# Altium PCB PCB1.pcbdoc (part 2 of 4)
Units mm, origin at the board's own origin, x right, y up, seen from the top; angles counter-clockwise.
Board outline 96.27 x 122.17 mm, 4 copper layers (Top Layer, Inner1, Inner2, Bottom Layer); 135 components, 133 nets, 720 pads, 358 vias.

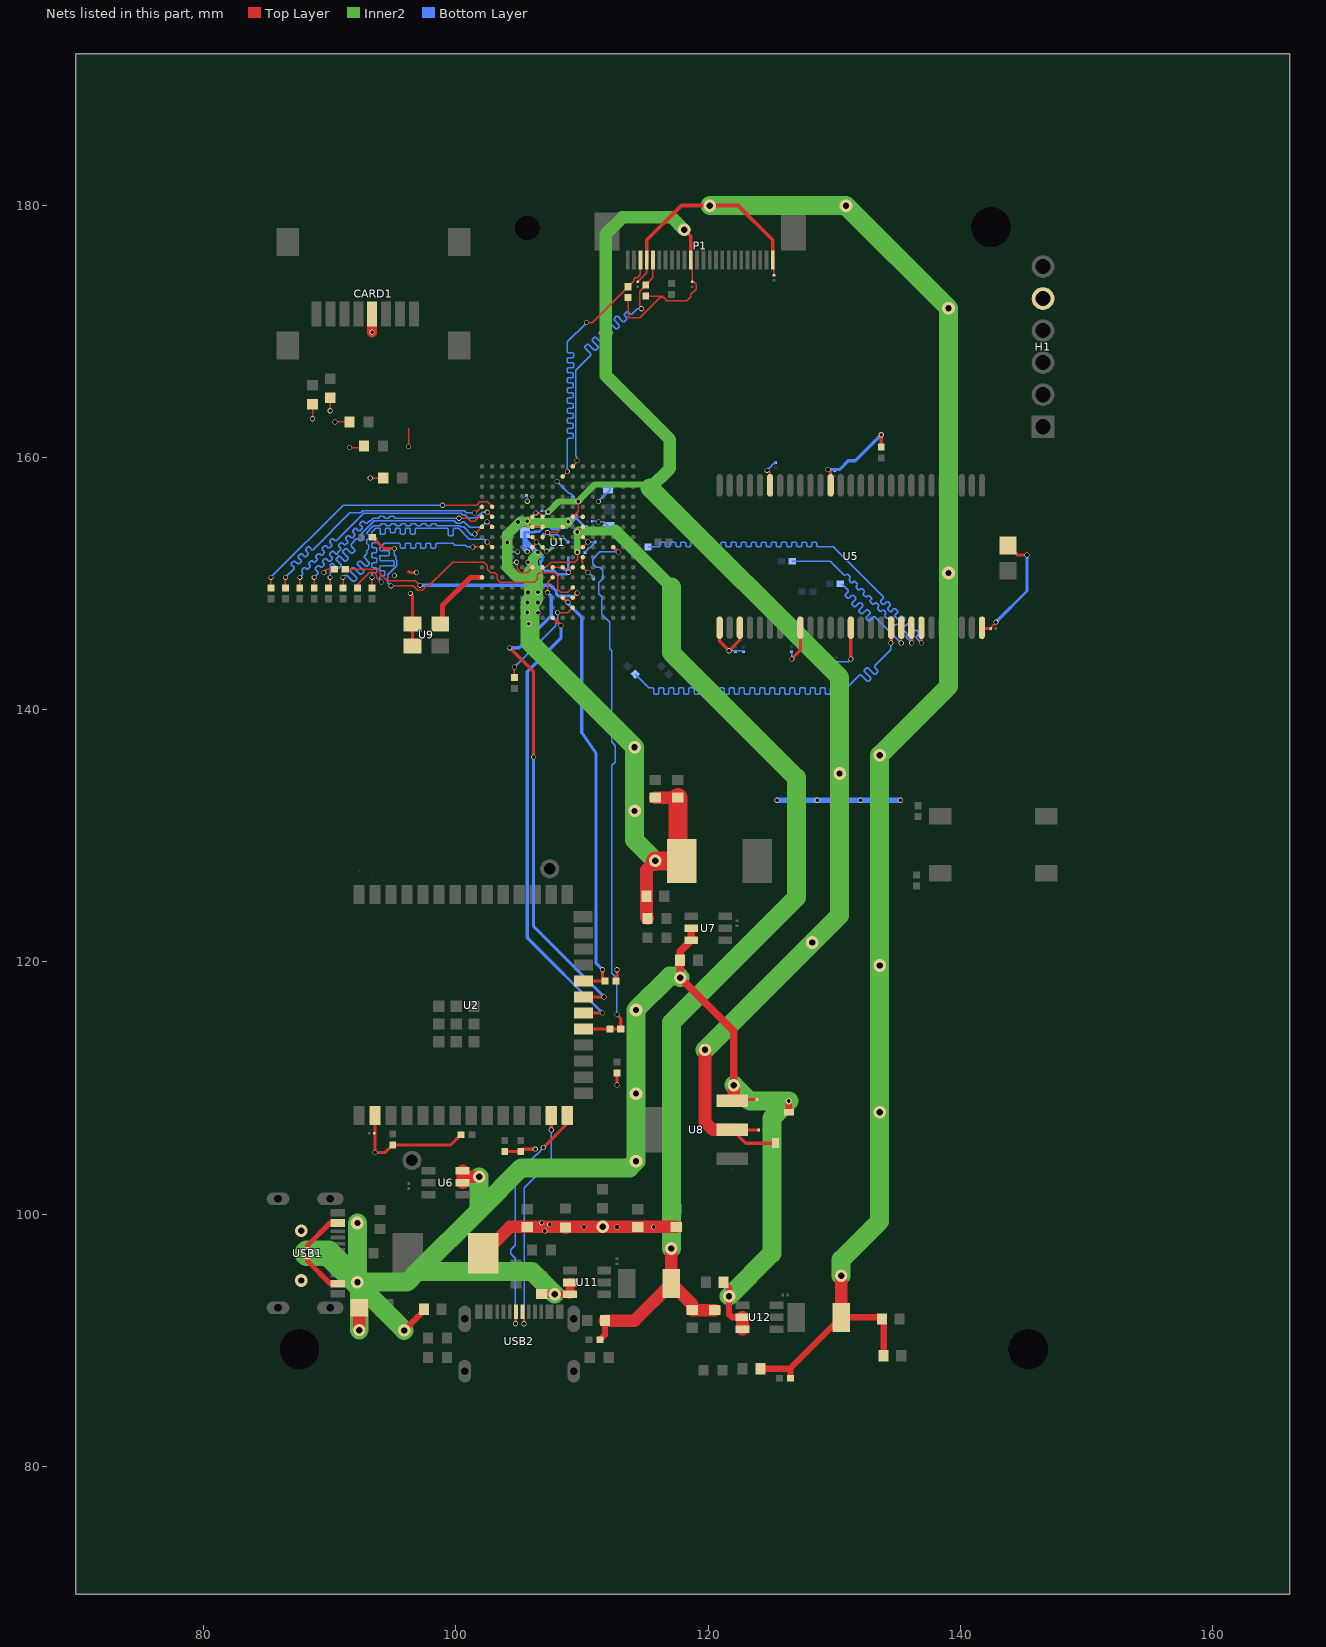
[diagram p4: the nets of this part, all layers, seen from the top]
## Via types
v1: diameter 0.4, hole 0.3, Top Layer to Bottom Layer, 324 vias
v2: diameter 1, hole 0.5, Top Layer to Bottom Layer, 33 vias
v3: diameter 0.5, hole 0.3, Top Layer to Bottom Layer, 1 vias

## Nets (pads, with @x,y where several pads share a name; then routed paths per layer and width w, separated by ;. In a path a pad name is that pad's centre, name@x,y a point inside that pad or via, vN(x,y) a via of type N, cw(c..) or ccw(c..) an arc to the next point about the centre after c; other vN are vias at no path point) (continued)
$1N71328: R50.2 U5.18 | length 41.7
  Top Layer w0.254: v1(134.493,145.288) 134.518,145.313 U5.18@134.518,146.504
  Bottom Layer w0.1: R50.2@114.225,142.823 115.316,141.732 115.616,141.732 115.687,141.661 115.687,141.295 115.757,141.224 116.016,141.224 116.087,141.295 116.087,141.661 116.157,141.732 116.416,141.732 116.487,141.661 116.487,141.295 116.557,141.224 116.816,141.224 116.887,141.295 116.887,141.661 116.957,141.732 117.216,141.732 117.287,141.661 117.287,141.295 117.357,141.224 117.616,141.224 117.687,141.295 117.687,141.661 117.757,141.732 118.016,141.732 118.087,141.661 118.087,141.295 118.157,141.224 118.416,141.224 118.487,141.295 118.487,141.661 118.557,141.732 118.816,141.732 118.887,141.661 118.887,141.295 118.957,141.224 119.216,141.224 119.287,141.295 119.287,141.661 119.357,141.732 119.616,141.732 119.687,141.661 119.687,141.295 119.757,141.224 120.016,141.224 120.087,141.295 120.087,141.661 120.157,141.732 120.416,141.732 120.487,141.661 120.487,141.295 120.557,141.224 120.816,141.224 120.887,141.295 120.887,141.661 120.957,141.732 121.216,141.732 121.287,141.661 121.287,141.295 121.357,141.224 121.616,141.224 121.687,141.295 121.687,141.661 121.757,141.732 122.016,141.732 122.087,141.661 122.087,141.295 122.157,141.224 122.416,141.224 122.487,141.295 122.487,141.661 122.557,141.732 122.816,141.732 122.887,141.661 122.887,141.295 122.957,141.224 123.216,141.224 123.287,141.295 123.287,141.661 123.357,141.732 123.616,141.732 123.687,141.661 123.687,141.295 123.757,141.224 124.016,141.224 124.087,141.295 124.087,141.661 124.157,141.732 124.416,141.732 124.487,141.661 124.487,141.295 124.557,141.224 124.816,141.224 124.887,141.295 124.887,141.661 124.957,141.732 125.216,141.732 125.287,141.661 125.287,141.295 125.357,141.224 125.616,141.224 125.687,141.295 125.687,141.661 125.757,141.732 126.016,141.732 126.087,141.661 126.087,141.295 126.157,141.224 126.416,141.224 126.487,141.295 126.487,141.661 126.557,141.732 126.816,141.732 126.887,141.661 126.887,141.295 126.957,141.224 127.216,141.224 127.287,141.295 127.287,141.661 127.357,141.732 127.616,141.732 127.687,141.661 127.687,141.295 127.757,141.224 128.016,141.224 128.087,141.295 128.087,141.661 128.157,141.732 128.416,141.732 128.487,141.661 128.487,141.295 128.557,141.224 128.816,141.224 128.887,141.295 128.887,141.661 128.957,141.732 129.216,141.732 129.287,141.661 129.287,141.295 129.357,141.224 129.616,141.224 129.687,141.295 129.687,141.661 129.757,141.732 130.985,141.732 132.014,142.761 132.114,142.761 132.625,142.25 132.725,142.25 132.908,142.433 132.908,142.533 132.397,143.044 132.397,143.144 132.579,143.327 132.679,143.327 133.191,142.816 133.291,142.816 133.473,142.998 133.473,143.098 133.199,143.373 133.199,143.473 134.493,144.768 v1(134.493,145.288)
$1N71371: R51.2 U5.19 | length 11.7
  Top Layer w0.1: v1(135.318,145.288) U5.19@135.318,146.504
  Bottom Layer w0.1: R51.2@130.627,149.958 131.119,149.466 131.119,149.366 130.881,149.127 130.881,149.027 131.064,148.844 131.164,148.844 131.402,149.083 131.502,149.083 131.714,148.871 131.714,148.771 131.395,148.453 131.395,148.353 131.578,148.17 131.678,148.17 131.997,148.489 132.097,148.489 132.28,148.306 132.28,148.206 131.961,147.887 131.961,147.787 132.144,147.604 132.244,147.604 132.563,147.923 132.663,147.923 132.845,147.74 132.845,147.64 132.527,147.321 132.527,147.221 132.71,147.039 132.81,147.039 133.128,147.357 133.228,147.357 135.17,145.415 135.191,145.415 v1(135.318,145.288)
$1N71457: R53.2 U5.21 | length 39.7
  Top Layer w0.254: v1(136.918,145.288) U5.21@136.918,146.504
  Bottom Layer w0.1: R53.2@115.241,152.908 116.151,152.908 116.222,152.979 116.222,153.218 116.293,153.289 116.551,153.289 116.622,153.218 116.622,152.979 116.693,152.908 116.951,152.908 117.022,152.979 117.022,153.218 117.093,153.289 117.351,153.289 117.422,153.218 117.422,152.979 117.493,152.908 117.751,152.908 117.822,152.979 117.822,153.218 117.893,153.289 118.151,153.289 118.222,153.218 118.222,152.979 118.293,152.908 118.551,152.908 118.622,152.979 118.622,153.218 118.693,153.289 118.951,153.289 119.022,153.218 119.022,152.979 119.093,152.908 119.351,152.908 119.422,152.979 119.422,153.218 119.493,153.289 119.751,153.289 119.822,153.218 119.822,152.979 119.893,152.908 120.151,152.908 120.222,152.979 120.222,153.218 120.293,153.289 120.551,153.289 120.622,153.218 120.622,152.979 120.693,152.908 120.951,152.908 121.022,152.979 121.022,153.218 121.093,153.289 121.351,153.289 121.422,153.218 121.422,152.979 121.493,152.908 121.751,152.908 121.822,152.979 121.822,153.218 121.893,153.289 122.151,153.289 122.222,153.218 122.222,152.979 122.293,152.908 122.551,152.908 122.622,152.979 122.622,153.218 122.693,153.289 122.951,153.289 123.022,153.218 123.022,152.979 123.093,152.908 123.351,152.908 123.422,152.979 123.422,153.218 123.493,153.289 123.751,153.289 123.822,153.218 123.822,152.979 123.893,152.908 124.151,152.908 124.222,152.979 124.222,153.218 124.293,153.289 124.551,153.289 124.622,153.218 124.622,152.979 124.693,152.908 124.951,152.908 125.022,152.979 125.022,153.218 125.093,153.289 125.351,153.289 125.422,153.218 125.422,152.979 125.493,152.908 125.751,152.908 125.822,152.979 125.822,153.218 125.893,153.289 126.151,153.289 126.222,153.218 126.222,152.979 126.293,152.908 126.551,152.908 126.622,152.979 126.622,153.218 126.693,153.289 126.951,153.289 127.022,153.218 127.022,152.979 127.093,152.908 127.351,152.908 127.422,152.979 127.422,153.218 127.493,153.289 127.751,153.289 127.822,153.218 127.822,152.979 127.893,152.908 128.151,152.908 128.222,152.979 128.222,153.218 128.293,153.289 128.551,153.289 128.622,153.218 128.622,152.979 128.693,152.908 129.921,152.908 133.892,148.937 133.892,148.837 133.68,148.626 133.68,148.526 133.863,148.343 133.963,148.343 134.175,148.554 134.275,148.554 134.458,148.371 134.458,148.271 134.246,148.06 134.246,147.96 134.429,147.777 134.529,147.777 134.74,147.989 134.84,147.989 135.023,147.806 135.023,147.706 134.812,147.494 134.812,147.394 134.995,147.211 135.095,147.211 135.306,147.423 135.406,147.423 135.589,147.24 135.589,147.14 135.377,146.929 135.377,146.829 135.56,146.646 135.66,146.646 135.872,146.857 135.972,146.857 136.155,146.674 136.155,146.574 135.943,146.363 135.943,146.263 136.126,146.08 136.226,146.08 136.437,146.292 136.537,146.292 136.72,146.109 136.72,146.009 136.509,145.797 136.509,145.697 v1(136.918,145.288)
$1N71500: R54.2 U5.20 | length 16.7
  Top Layer w0.254: U5.20@136.118,146.504 136.144,146.478 v1(136.144,145.288)
  Bottom Layer w0.1: R54.2@126.671,151.763 129.669,151.763 130.793,150.639 130.893,150.639 130.983,150.73 131.083,150.73 131.266,150.547 131.266,150.447 131.176,150.356 131.176,150.256 131.358,150.074 131.458,150.074 131.549,150.164 131.649,150.164 131.832,149.981 131.832,149.881 131.741,149.791 131.741,149.691 131.924,149.508 132.024,149.508 132.115,149.598 132.215,149.598 132.397,149.416 132.397,149.316 132.307,149.225 132.307,149.125 132.49,148.942 132.59,148.942 132.68,149.033 132.78,149.033 132.963,148.85 132.963,148.75 132.873,148.659 132.873,148.559 133.055,148.377 133.155,148.377 133.246,148.467 133.346,148.467 133.529,148.284 133.529,148.184 133.438,148.094 133.438,147.994 133.621,147.811 133.721,147.811 133.812,147.901 133.912,147.901 134.095,147.718 134.095,147.618 134.004,147.528 134.004,147.428 134.187,147.245 134.287,147.245 134.377,147.336 134.477,147.336 134.66,147.153 134.66,147.053 134.57,146.962 134.57,146.862 134.753,146.679 134.853,146.679 134.943,146.77 135.043,146.77 135.226,146.587 135.226,146.487 135.135,146.397 135.135,146.297 135.318,146.114 135.418,146.114 135.509,146.204 135.609,146.204 135.792,146.021 135.792,145.921 135.701,145.831 135.701,145.731 v1(136.144,145.288)
$2N5507: R23.2 U1.P10 | length 20.1
  Top Layer w0.1: R23.2@91.238,151.13 93.853,151.13 93.959,151.024 93.959,150.836 94.575,150.22 96.795,150.22 v1(97.155,149.86)
  Top Layer w0.254: U1.P10@109.277,148.889 109.601,149.213 v1@109.601,149.225
  Bottom Layer w0.254: v1(97.155,149.86) 107.507,149.86 107.986,149.381 107.986,149.159 108.127,149.018 109.073,149.018 109.173,148.918 109.294,148.918 v1(109.622,149.246)
$2N5509: R24.2 U1.N10 | length 24
  Top Layer w0.1: v1(94.869,149.818) 96.628,149.818 96.988,149.458 97.322,149.458 97.682,149.818 97.875,149.818 99.119,151.062 99.119,151.067 99.759,151.707 102.199,151.707 102.495,151.411 102.495,151.131 102.755,150.871 103.091,150.871 103.295,150.667 103.295,150.331 103.519,150.107 105.435,150.107 105.442,150.114 105.912,150.114 105.919,150.107 106.235,150.107 106.459,150.331 106.459,150.689 106.641,150.871 107.835,150.871 108.095,150.611 108.095,149.531 108.319,149.307 108.895,149.307 U1.N10@109.277,149.689
  Top Layer w0.254: R24.2@93.397,153.67 94.286,152.781 v1(95.123,152.781)
  Bottom Layer w0.1: v1(94.869,149.818) 94.615,150.072 94.615,150.697 95.323,151.405 95.323,151.829 95.25,151.902 95.25,152.146 95.123,152.273 v1(95.123,152.781)
$2N5511: R25.2 U1.R10 | length 7.9
  Top Layer w0.1: R25.2@104.648,142.546 v1(104.648,143.383) ; v1(108.077,147.701) 108.889,147.701 U1.R10@109.277,148.089
  Bottom Layer w0.1: v1(104.648,143.383) 107.929,146.664 107.929,146.852 108.077,147 v1(108.077,147.701)
+1V1: C25.2 C27.2 C28.2 C41.1 C42.1 C43.1 C44.1 C49.1 C53.1 C54.1 C61.1 L2.2 R15.2 U1.G6 U1.G7 U1.L8 U1.L9 U1.L10 | length 71.4
  Top Layer w0.1: v1@105.664,154.94 105.664,154.902 U1.G6@106.077,154.489 U1.G7@106.877,154.489 ; U1.L8@107.677,151.289 U1.L9@108.477,151.289 108.543,151.289 v1(108.936,150.897) 109.277,151.238 U1.L10@109.277,151.289
  Top Layer w1: R15.2@115.198,123.444 115.124,123.518 C25.2@115.124,125.222 115.124,127.316 v2(115.824,128.016) ; C27.2@115.824,133.031 C28.2@117.602,133.031
  Top Layer w1.5: v2(115.824,128.016) L2.2@117.904,128.016 117.602,128.318 C28.2@117.602,133.031
  Inner2 w0.7: 105.232,154.932 v1(105.672,154.932)
  Inner2 w0.8: v1(104.086,153.249) v1@104.077,153.258 ; 105.232,154.932 105.21,154.909 105.111,154.909 104.077,153.875 v1@104.077,153.258 ; v1@105.672,154.909 105.777,154.805 106.053,154.805 106.069,154.789 108.815,154.789 v1(108.92,154.894) ; v1@106.436,152.302 106.125,151.99 106.125,150.859 105.705,150.439 104.877,150.439 104.077,151.239 v1@104.077,153.258
  Inner2 w1.5: 106.125,150.859 106.172,150.812 106.172,148.785 105.895,148.508 105.895,145.311 v2(114.173,137.033) v2(114.173,131.972) 114.173,129.667 v2(115.824,128.016)
  Bottom Layer w0.2: 105.475,153.518 C61.1@105.475,154.051 106.24,154.051 C41.1@106.299,154.11 106.607,154.11 106.986,154.489 107.461,154.489 107.661,154.289 108.082,154.289 C42.1@108.342,154.548 108.458,154.432 108.78,154.432 109.542,155.194 ; v1(106.514,152.479) 106.642,152.479 106.736,152.385 106.736,152.381 106.842,152.275 106.842,151.859 C54.1@106.748,151.765 106.748,151.316 107.061,151.003 107.819,151.003 108.073,150.749 108.788,150.749 108.801,150.762 v1@108.936,150.762 ; C53.1@108.653,151.13 108.78,151.003 108.839,151.003 108.907,150.935 C49.1@108.907,152.019 ; C43.1@109.542,155.448 109.542,155.194 ; C44.1@110.558,154.178 110.525,154.211 110.525,154.392 110.377,154.54 110.196,154.54 109.542,155.194
  Bottom Layer w0.4: 105.475,153.409 106.405,152.479 v1(106.514,152.479) ; 105.475,153.518 105.475,152.716 v1(105.666,152.525)
  other v1: 105.791,146.812 105.664,147.701 106.527,147.689 106.526,148.489 105.661,148.508 105.726,149.289 106.508,149.306 105.727,151.69 104.926,154.888
+1V8: C29.1 C32.2 C35.1 C62.1 C63.1 P1.11 pad.55@123.394,105.627 R38.2 R39.2 U1.F10 U1.F11 U8.2 | length 126.3
  Top Layer w0.1: v1(109.709,156.504) 109.709,156.262 109.695,156.247 109.695,155.931 109.709,155.917 109.709,155.721 U1.F10@109.277,155.289 U1.F11@110.077,155.289 ; R38.2@113.665,172.668 113.665,172.205 113.661,172.201 113.661,171.2 113.792,171.069 114.574,171.069 116.173,172.668 116.509,172.668 ; R39.2@115.062,172.795 116.382,172.795 116.509,172.668 ; P1.11@118.634,175.655 118.733,175.557 118.733,174.458 118.745,174.446 C35.1@118.745,173.931 ; 118.856,173.931 119.057,173.73 119.057,173.352 118.639,172.934 118.639,172.756 118.321,172.437 116.74,172.437 116.509,172.668
  Top Layer w0.254: C29.1@124.011,106.68 121.943,106.68 122.996,105.627 pad.55@123.394,105.627 C32.2@125.349,105.627
  Top Layer w0.3: v2(118.11,178.054) 118.634,177.53 P1.11@118.634,175.655
  Top Layer w1: v2(119.761,113.03) 119.761,107.315 120.367,106.709 U8.2@121.914,106.709
  Inner2 w0.5: v1(107.325,155.689) 107.362,155.689 108.178,156.504 v1(109.709,156.504) 109.888,156.683 109.888,156.713 111.036,157.861 115.379,157.861
  Inner2 w1: 115.411,157.575 116.967,159.131 116.967,161.417 111.887,166.497 111.887,177.71 113.21,179.033 117.131,179.033 v2(118.11,178.054)
  Inner2 w1.5: 115.411,157.575 130.429,142.558 v2(130.429,134.939) 130.429,123.698 v2(128.27,121.539) v2(119.761,113.03)
  Bottom Layer w0.1: C63.1@106.807,155.761 107.253,155.761 v1(107.325,155.689) 106.934,155.298 C62.1@106.934,155.262
+2V5: C65.2 C67.2 C68.2 L3.2 R41.2 U1.G11 U1.L7 | length 91.3
  Top Layer w0.1: U1.L7@106.877,151.289 107.137,151.289 107.555,151.707 109.435,151.707 109.659,151.931 109.659,152.247 109.629,152.277 v1(109.629,152.489) ; v1(109.629,154.089) 110.029,154.489 U1.G11@110.077,154.489
  Top Layer w0.5: R41.2@111.431,90.043 111.825,90.437 C65.2@111.825,91.567
  Top Layer w1: C65.2@111.825,91.567 114.17,91.567 L3.2@117.091,94.488 ; v2(117.091,97.282) L3.2@117.091,94.488 ; C67.2@120.523,92.394 C68.2@118.745,92.394 118.745,92.834 L3.2@117.091,94.488
  Inner2 w0.5: v1(109.629,152.489) v1(109.629,154.089)
  Inner2 w0.7: v1(109.629,154.089) 109.718,154.178 112.649,154.178
  Inner2 w1: 112.649,154.178 117.091,149.736
  Inner2 w1.5: v2(117.091,97.282) 117.091,115.186 127,125.095 127,134.62 117.091,144.529 117.091,149.736
+2V8: C34.1 C70.2 C72.2 C73.2 C74.1 L4.2 P1.4 P1.24 R47.2 | length 139.5
  Top Layer w0.1: C34.1@114.427,173.931 115.135,174.639 P1.4@115.135,175.655 ; P1.24@125.136,175.652 125.222,175.566 C74.1@125.222,174.439
  Top Layer w0.3: P1.4@115.135,175.655 115.135,177.23 117.885,179.98 122.383,179.98 125.136,177.227 P1.24@125.136,175.652
  Top Layer w0.5: C70.2@124.144,87.757 126.489,87.757 ; R47.2@126.544,86.995 126.544,87.702 126.489,87.757 ; C73.2@133.793,91.694 133.666,91.821 L4.2@130.553,91.821 126.489,87.757 ; C72.2@133.92,88.773 C73.2@133.92,91.567
  Top Layer w1: L4.2@130.556,91.824 v2(130.556,95.123)
  Inner2 w1.5: v2(120.142,179.959) v2(130.937,179.959) v2(139.065,171.831) v2(139.065,150.833) 139.065,141.859 v2(133.604,136.398) v2(133.604,119.716) v2(133.604,108.091) 133.604,99.441 130.556,96.393 v2(130.556,95.123)
+3V3: C8.1 C10.1 C11.1 C12.1 C13.1 C14.1 C15.2 C16.2 C17.2 C19.2 C22.2 C23.2 C37.1 C39.1 C40.1 C45.1 C46.1 C47.1 C48.1 C50.1 C51.1 C52.1 C55.1 C56.1 C57.1 C58.1 C59.1 CARD1.4 H1.5 L1.2 R1.2 R3.1 R4.1 R5.2 R7.2 R11.2 R16.2 R17.2 R18.2 R19.2 R20.2 R21.2 R22.2 R23.1 U1.F6 U1.F7 U1.G9 U1.H6 U1.H7 U1.H11 U1.J6 U1.J7 U1.J11 U1.K11 U1.L6 U1.L11 U2.2 U5.1 U5.3 U5.9 U5.14 U5.27 U5.43 U5.49 U9.1 U9.4 | length 113.5
  Top Layer w0.1: v1(88.646,163.068) R19.2@88.646,164.22 ; v1(89.537,150.887) 89.78,151.13 R23.1@90.372,151.13 ; v1(90.043,163.703) R18.2@90.043,164.728 ; v1(90.424,162.814) R20.2@91.576,162.814 ; v1(91.567,160.782) 92.592,160.782 R17.2@92.719,160.909 ; v1(93.218,158.369) R16.2@94.243,158.369 ; v1@96.275,160.909 96.275,162.306 ; v1(104.829,151.689) 104.859,151.659 104.859,151.167 105.15,150.876 105.664,150.876 U1.L6@106.077,151.289 ; U1.J6@106.077,152.889 106.405,153.217 v1(106.405,153.288) 106.405,153.361 U1.H6@106.077,153.689 ; U1.F6@106.077,155.289 106.345,155.557 v1(106.345,155.607) 106.559,155.607 U1.F7@106.877,155.289 ; U1.J7@106.877,152.889 107.188,152.578 v1@107.188,152.527 ; U1.H7@106.877,153.689 106.926,153.689 v1(107.274,154.037) 107.484,154.037 107.519,154.071 107.835,154.071 107.881,154.025 108.013,154.025 U1.G9@108.477,154.489 ; U1.K11@110.077,152.089 110.077,151.962 109.982,151.867 109.982,151.765 110.077,151.67 U1.L11@110.077,151.289 v1(110.49,150.876) ; U1.J11@110.077,152.889 110.477,153.289 v1(110.49,153.289) 110.09,153.689 U1.H11@110.077,153.689 ; v1(124.674,158.977) 124.741,158.977 124.918,158.8 U5.49@124.918,157.788 ; C14.1@142.426,146.431 142.509,146.514 142.509,146.625 142.627,146.743 142.738,146.743 142.816,146.821 v1(142.816,146.939)
  Top Layer w0.254: U2.2@93.721,107.836 93.599,107.714 v1(93.599,104.902) 94.413,104.902 R7.2@94.996,105.485 99.591,105.485 R5.2@100.405,106.299 ; 96.271,150.952 96.346,150.876 v1(96.901,150.876) ; v1(96.393,149.225) 96.563,149.055 U9.4@96.563,146.798 U9.1@96.563,145.048 ; R21.2@103.886,104.977 R22.2@105.156,104.977 105.335,105.156 v1(106.299,105.156) ; R3.1@112.701,118.491 112.776,118.566 v1(112.776,119.38) ; v1(112.776,110.236) R4.1@112.776,111.2 ; U5.1@120.918,146.631 120.918,145.422 v1(121.666,144.674) 122.518,145.526 U5.3@122.518,146.504 ; v1(126.638,144.028) 127.318,144.707 U5.9@127.318,146.504 ; v1(129.5,159.044) 129.718,158.826 U5.43@129.718,157.788 ; v1(131.318,144.018) U5.14@131.318,146.504 ; R1.2@133.731,160.834 v1(133.731,161.798) ; U5.27@141.718,146.504 141.791,146.431 C14.1@142.426,146.431 ; C8.1@143.764,153.019 144.51,152.273 v1(145.288,152.273)
  Top Layer w0.8: v1(93.372,169.926) CARD1.4@93.372,171.374
  Top Layer w1: L1.2@102.187,96.901 104.281,98.995 C19.2@105.664,98.995 108.659,98.995 R11.2@108.712,98.942 108.765,98.995 v1(110.161,98.995) v2(111.647,98.995) v1(112.775,98.995) C23.2@114.427,98.995 v1(115.692,98.995) C22.2@117.475,98.995
  Inner2 w0.1: v1(106.405,153.288) 106.468,153.288 v1(107.188,152.568) 107.412,152.568 108.041,153.198 108.041,153.269 v1(107.274,154.037)
  Bottom Layer w0.1: C51.1@104.208,151.638 104.778,151.638 v1(104.829,151.689) ; C56.1@104.462,152.527 104.886,152.527 v1(104.894,152.519) ; C37.1@105.605,156.972 105.664,156.913 v1(105.664,156.524) ; C45.1@106.934,153.865 107.102,153.865 v1(107.274,154.037) 107.455,153.855 108.071,153.855 108.189,153.737 108.189,153.626 C46.1@108.272,153.543 108.644,153.543 C47.1@108.898,153.289 ; v1(107.188,152.568) 107.288,152.568 C57.1@107.628,152.908 ; C50.1@108.018,156.464 109.018,156.464 109.205,156.651 109.205,156.762 C39.1@109.288,156.845 109.288,156.956 109.087,157.157 108.961,157.157 v1(108.029,158.089) ; C52.1@110.236,152.468 C55.1@111.057,153.289 v1(110.49,153.289) ; v1(110.49,150.876) 110.686,150.68 110.738,150.68 110.939,150.479 C48.1@110.939,150.368 ; C40.1@110.812,154.94 111.274,154.94 v1(111.323,154.89) 111.745,154.89 C59.1@112.141,154.494 ; v1(111.301,156.512) 112.206,157.417 C58.1@112.206,157.607 ; v1(121.666,144.674) 121.974,144.674 121.98,144.668 122.726,144.668 C11.1@122.809,144.585 ; v1(124.674,158.977) 125.037,159.34 125.037,159.379 125.155,159.497 125.266,159.497 C16.2@125.349,159.58 ; C12.1@126.619,144.585 126.638,144.566 v1(126.638,144.028) ; C13.1@129.91,143.88 130.028,143.88 130.106,143.802 131.102,143.802 v1(131.318,144.018)
  Bottom Layer w0.254: v1(129.5,159.044) 130.427,159.044 131.12,159.737 131.67,159.737 v1(133.731,161.798) ; v1(142.816,146.939) 145.288,149.411 v1(145.288,152.273)
  Bottom Layer w0.4: v1(125.476,132.821) v1(128.651,132.821) v1(132.08,132.821) v1(135.255,132.821)
  other v1: 107.061,98.679 107.442,99.187 106.807,99.314 95.123,150.636 96.241,160.876
+5V: C20.2 C26.2 C30.1 C31.2 C33.2 C66.2 C71.2 U6.2 U6.3 U7.2 U7.3 U8.3 U11.2 U11.3 U12.2 U12.3 USB1.A4B9 USB1.B4A9 | length 137.8
  Top Layer w0.254: U8.3@122.301,109.093 C30.1@123.884,109.093
  Top Layer w0.4: USB1.B4A9@90.627,94.501 90.03,94.501 88.227,96.304 88.227,97.508 90.02,99.301 USB1.A4B9@90.627,99.301
  Top Layer w0.5: v2(95.904,90.786) 97.471,92.353 C20.2@97.471,92.456 ; C66.2@106.807,93.661 v2(107.842,93.661) 109.042,93.661 U11.3@109.066,93.637 ; C71.2@121.223,94.615 121.666,94.172 v2(121.666,93.492) 121.666,92.075 121.92,91.821 U12.2@122.729,91.821 ; C31.2@126.402,108.077 v3(126.402,108.966)
  Top Layer w0.6: U7.2@118.665,122.682 U7.3@118.665,121.732 117.791,120.858 C26.2@117.791,120.142 v2(117.791,118.745) 122.047,114.489 v2(122.047,110.236)
  Top Layer w0.7: U11.3@109.066,93.637 U11.2@109.066,94.587
  Top Layer w1: v2(92.345,90.805) C33.2@92.345,92.583 ; U6.2@100.537,102.491 100.537,102.97 ; U6.3@100.537,103.439 100.537,102.97 ; v2(101.854,102.97) 100.537,102.97 ; U8.3@121.914,109.009 122.047,109.142 v2(122.047,110.236) ; U12.3@122.729,90.871 U12.2@122.729,91.819
  Inner2 w1.5: v2(92.202,99.301) v2(92.202,94.615) 96.139,94.615 96.987,95.463 ; v2(92.345,90.805) 92.345,94.091 92.202,94.234 92.456,94.234 v2(95.904,90.786) ; v2(101.854,102.97) 101.854,100.33 ; v2(107.842,93.661) 106.04,95.463 96.987,95.463 ; v2(117.791,118.745) 117.664,118.872 116.964,118.872 v2(114.286,116.194) v2(114.286,109.562) v2(114.286,104.198) 113.761,103.673 105.197,103.673 101.854,100.33 ; v2(121.666,93.492) 125.062,96.888 125.062,107.626 v3(126.402,108.966) 123.317,108.966 v2(122.047,110.236) ; 96.987,95.463 101.854,100.33
  Inner2 w2: v2(88.213,96.901) 89.916,96.901 v2(92.202,94.615)
  other v2: 87.757,94.742 87.757,98.679
CCLK: R6.1 R6.2 U1.J14 U2.19 | length 44.6
  Top Layer w0.254: U2.19@110.241,114.681 R6.1@112.216,114.681 R6.2@113.082,114.681 113.082,115.518 v1(112.776,115.824) ; U1.J14@112.477,152.889 112.86,152.506 v1(112.903,152.506)
  Bottom Layer w0.1: v1(112.776,115.824) 112.776,118.703 112.374,119.105 112.374,135.577 112.649,135.852 112.649,137.16 112.395,137.414 112.374,137.414 112.374,144.674 112.222,144.826 112.222,146.928 111.564,147.586 111.564,148.951 111.335,149.18 111.335,150.07 111.654,150.389 111.654,151.043 111.419,151.278 111.133,151.278 110.848,151.562 110.848,151.93 111.424,152.506 v1(112.903,152.506)
CRYSTAL: U1.M1 U9.3 | length 5.6
  Top Layer w0.4: U9.3@98.763,146.798 98.933,146.968 98.933,148.256 101.162,150.485 101.209,150.485 101.213,150.489 U1.M1@102.077,150.489
D0: R26.1 U1.E2 | length 21
  Top Layer w0.1: R26.1@85.344,149.658 v1(85.344,150.495) ; v1@98.933,156.21 101.658,156.21 101.919,156.471 102.495,156.471 U1.E2@102.877,156.089
  Bottom Layer w0.1: v1(85.344,150.495) 91.059,156.21 v1(98.943,156.21)
D1: R27.1 U1.E1 | length 21.1
  Top Layer w0.1: R27.1@86.487,149.658 v1(86.487,150.495) ; v1(101.473,155.604) 101.592,155.604 U1.E1@102.077,156.089
  Bottom Layer w0.1: v1(86.487,150.495) 87.172,151.18 87.172,151.28 86.955,151.498 86.955,151.598 87.137,151.78 87.237,151.78 87.455,151.563 87.555,151.563 87.738,151.746 87.738,151.846 87.52,152.063 87.52,152.163 87.703,152.346 87.803,152.346 88.021,152.129 88.121,152.129 88.303,152.311 88.303,152.411 88.086,152.629 88.086,152.729 88.269,152.912 88.369,152.912 88.586,152.694 88.686,152.694 91.596,155.604 92.456,155.604 92.634,155.782 100.666,155.782 100.844,155.604 v1(101.473,155.604)
D2: R28.1 U1.F2 | length 21
  Top Layer w0.1: R28.1@87.63,149.658 v1(87.63,150.495) ; v1(102.486,155.659) 102.507,155.659 U1.F2@102.877,155.289
  Bottom Layer w0.1: v1(87.63,150.495) 87.884,150.749 87.884,150.849 87.78,150.953 87.78,151.053 87.963,151.236 88.063,151.236 88.167,151.132 88.267,151.132 88.45,151.315 88.45,151.415 88.346,151.519 88.346,151.619 88.529,151.802 88.629,151.802 88.733,151.698 88.833,151.698 89.015,151.88 89.015,151.98 88.911,152.084 88.911,152.184 89.094,152.367 89.194,152.367 89.298,152.263 89.398,152.263 89.581,152.446 89.581,152.546 89.427,152.7 89.427,152.8 89.61,152.983 89.71,152.983 89.864,152.829 89.964,152.829 90.147,153.012 90.147,153.112 89.993,153.266 89.993,153.366 90.176,153.549 90.276,153.549 90.43,153.395 90.53,153.395 92.717,155.582 100.414,155.582 100.524,155.473 100.692,155.473 100.963,155.202 101.64,155.202 102.096,155.659 v1(102.486,155.659)
D3: R29.1 U1.F1 | length 21
  Top Layer w0.1: R29.1@88.773,149.658 v1(88.773,150.495) ; v1(100.248,155.18) 100.947,155.18 101.179,154.948 101.513,154.948 101.871,155.306 102.06,155.306 U1.F1@102.077,155.289
  Bottom Layer w0.1: v1(88.773,150.495) 89.092,150.814 89.092,150.914 88.875,151.132 88.875,151.232 89.058,151.415 89.158,151.415 89.277,151.295 89.377,151.295 89.56,151.478 89.56,151.578 89.44,151.697 89.44,151.797 89.623,151.98 89.723,151.98 89.941,151.763 90.041,151.763 90.224,151.946 90.224,152.046 90.006,152.263 90.006,152.363 90.189,152.546 90.289,152.546 90.507,152.329 90.607,152.329 90.659,152.381 90.659,152.477 90.871,152.69 90.871,152.79 90.702,152.959 90.702,153.059 90.885,153.242 90.985,153.242 91.154,153.072 91.254,153.072 91.437,153.255 91.437,153.355 91.268,153.525 91.268,153.625 91.45,153.807 91.55,153.807 91.72,153.638 91.82,153.638 92.003,153.821 92.003,153.921 91.833,154.09 91.833,154.19 92.016,154.373 92.116,154.373 92.285,154.204 92.385,154.204 92.568,154.387 92.568,154.487 92.399,154.656 92.399,154.756 92.582,154.939 92.682,154.939 92.851,154.769 92.951,154.769 93.16,154.978 93.256,154.978 93.458,155.18 93.853,155.18 93.924,155.251 93.924,155.277 93.995,155.348 94.253,155.348 94.324,155.277 94.324,155.251 94.395,155.18 94.653,155.18 94.724,155.251 94.724,155.277 94.795,155.348 95.053,155.348 95.124,155.277 95.124,155.251 95.195,155.18 v1(100.248,155.18)
D4: R30.1 U1.G2 | length 21
  Top Layer w0.1: R30.1@89.916,149.658 90.043,149.785 v1(90.043,150.495) ; v1(102.471,154.892) 102.474,154.892 U1.G2@102.877,154.489
  Bottom Layer w0.1: v1(90.043,150.495) 90.043,151.482 90.189,151.628 90.207,151.628 90.619,151.216 90.719,151.216 90.902,151.399 90.902,151.499 90.49,151.911 90.49,151.929 90.755,152.194 90.773,152.194 91.185,151.782 91.285,151.782 91.468,151.965 91.468,152.065 91.056,152.477 91.056,152.577 91.239,152.76 91.339,152.76 91.701,152.398 91.801,152.398 91.983,152.581 91.983,152.681 91.694,152.97 91.694,153.133 92.12,153.559 92.22,153.559 92.388,153.391 92.488,153.391 92.671,153.573 92.671,153.673 92.503,153.842 92.503,153.942 93.541,154.98 99.879,154.98 100.081,154.778 100.414,154.778 100.541,154.905 100.65,154.905 101.102,154.453 102.031,154.453 v1(102.471,154.892)
D5: R31.1 U1.G1 | length 21
  Top Layer w0.1: R31.1@91.059,149.658 v1(91.059,150.495) ; v1(101.507,153.924) 101.512,153.924 U1.G1@102.077,154.489
  Bottom Layer w0.1: v1(91.059,150.495) 91.238,150.674 91.338,150.674 91.847,150.165 91.947,150.165 92.13,150.348 92.13,150.448 91.621,150.957 91.621,151.057 91.803,151.239 91.903,151.239 92.413,150.73 92.513,150.73 92.695,150.913 92.695,151.013 92.186,151.522 92.186,151.622 92.35,151.786 92.45,151.786 92.862,151.374 92.962,151.374 93.145,151.556 93.145,151.656 92.733,152.069 92.733,152.169 92.933,152.369 92.933,152.627 93.004,152.697 93.045,152.697 93.116,152.768 93.116,153.027 93.045,153.097 93.004,153.097 92.933,153.168 92.933,153.427 93.004,153.497 93.045,153.497 93.116,153.568 93.116,153.827 93.045,153.897 93.004,153.897 92.933,153.968 92.933,154.042 93.379,154.488 93.401,154.488 93.491,154.578 93.976,154.578 94.047,154.649 94.047,154.68 94.118,154.751 94.376,154.751 94.447,154.68 94.447,154.649 94.518,154.578 94.776,154.578 94.847,154.649 94.847,154.68 94.918,154.751 95.176,154.751 95.247,154.68 95.247,154.649 95.318,154.578 95.576,154.578 95.647,154.649 95.647,154.68 95.718,154.751 95.976,154.751 96.047,154.68 96.047,154.649 96.118,154.578 96.376,154.578 96.447,154.649 96.447,154.68 96.518,154.751 96.776,154.751 96.847,154.68 96.847,154.649 96.918,154.578 97.176,154.578 97.247,154.649 97.247,154.68 97.318,154.751 97.576,154.751 97.647,154.68 97.647,154.649 97.718,154.578 97.976,154.578 98.047,154.649 98.047,154.68 98.118,154.751 98.376,154.751 98.447,154.68 98.447,154.649 98.518,154.578 100.302,154.578 100.392,154.488 100.621,154.488 101.275,153.834 101.417,153.834 v1(101.507,153.924)
D6: R32.1 U1.J1 | length 20.9
  Top Layer w0.1: R32.1@92.202,149.658 92.202,149.921 93.178,150.897 93.512,150.897 93.747,150.662 93.747,150.474 v1(94.107,150.114) ; v1(101.346,152.908) 102.058,152.908 U1.J1@102.077,152.889
  Bottom Layer w0.1: v1(94.107,150.114) 93.959,150.262 93.959,150.546 94.03,150.617 94.294,150.617 94.365,150.687 94.365,150.946 94.294,151.017 94.03,151.017 93.959,151.087 93.959,151.346 94.03,151.417 95.052,151.417 95.123,151.487 95.123,151.746 95.052,151.817 94.03,151.817 93.959,151.887 93.959,152.146 94.03,152.217 94.671,152.217 94.742,152.287 94.742,152.546 94.671,152.617 94.03,152.617 93.959,152.687 93.959,152.821 94.321,153.183 95.539,153.183 95.61,153.112 95.61,152.852 95.68,152.781 95.939,152.781 96.01,152.852 96.01,153.112 96.08,153.183 96.339,153.183 96.41,153.112 96.41,152.852 96.48,152.781 96.739,152.781 96.81,152.852 96.81,153.112 96.88,153.183 97.139,153.183 97.21,153.112 97.21,152.852 97.28,152.781 97.539,152.781 97.61,152.852 97.61,153.112 97.68,153.183 97.939,153.183 98.01,153.112 98.01,152.852 98.08,152.781 98.339,152.781 98.41,152.852 98.41,153.112 98.48,153.183 99.801,153.183 99.928,153.056 100.751,153.056 100.899,152.908 v1(101.346,152.908)
D7: R34.1 U1.J2 | length 21
  Top Layer w0.1: R34.1@93.345,149.658 v1(93.345,150.495) ; v1(102.489,153.289) 102.489,153.277 U1.J2@102.877,152.889
  Bottom Layer w0.1: v1(93.345,150.495) 93.345,150.769 93.416,150.84 93.659,150.84 93.73,150.911 93.73,151.169 93.659,151.24 93.416,151.24 93.345,151.311 93.345,151.569 93.416,151.64 93.659,151.64 93.73,151.711 93.73,151.969 93.659,152.04 93.416,152.04 93.345,152.111 93.345,152.369 93.416,152.44 93.659,152.44 93.73,152.511 93.73,152.769 93.659,152.84 93.416,152.84 93.345,152.911 93.345,153.169 93.416,153.24 93.659,153.24 93.73,153.311 93.73,153.569 93.659,153.64 93.416,153.64 93.345,153.711 93.345,154.051 93.672,154.378 93.921,154.378 93.991,154.307 93.991,153.969 94.062,153.898 94.321,153.898 94.391,153.969 94.391,154.307 94.462,154.378 94.721,154.378 94.791,154.307 94.791,154.11 94.862,154.04 95.121,154.04 95.191,154.11 95.191,154.307 95.262,154.378 95.521,154.378 95.591,154.307 95.591,153.969 95.662,153.898 95.921,153.898 95.991,153.969 95.991,154.307 96.062,154.378 96.321,154.378 96.391,154.307 96.391,153.969 96.462,153.898 96.721,153.898 96.791,153.969 96.791,154.307 96.862,154.378 99.316,154.378 99.386,154.307 99.386,153.868 99.457,153.797 99.716,153.797 99.786,153.868 99.786,154.307 99.857,154.378 100.22,154.378 101.076,153.522 102.256,153.522 v1(102.489,153.289)
DIN: U1.T8 U2.20 | length 36.6
  Top Layer w0.254: U1.T8@107.677,147.289 107.727,147.289 v1(108.331,146.685) ; U2.20@110.241,115.951 v1(111.633,115.951)
  Bottom Layer w0.254: v1(108.331,146.685) 108.331,145.669 105.664,143.002 105.664,121.92 v1(111.633,115.951)
DN: U2.13 USB2.A7 | length 18.5
  Top Layer w0.1: USB2.A7@105.279,92.278 105.41,92.147 v1(105.41,91.313)
  Top Layer w0.254: v1(107.569,106.68) 107.569,107.714 U2.13@107.691,107.836
  Bottom Layer w0.1: v1(105.41,91.313) 105.41,102.108 107.569,104.267 v1(107.569,106.68)
DONE: pad.55@110.617,137.16 R3.2 U1.P9 U2.22 | length 33.3
  Top Layer w0.254: U1.P9@108.477,148.889 108.847,148.519 v1(108.895,148.519) ; U2.22@110.241,118.491 R3.2@111.835,118.491 111.633,118.693 v1(111.633,119.38)
  Bottom Layer w0.254: v1(108.895,148.519) 108.895,148.407 109.982,147.32 109.982,138.176 111.125,136.525 111.125,119.888 v1(111.633,119.38)
DOUT: U1.M8 U2.21 | length 40
  Top Layer w0.1: v1(107.277,149.274) 107.277,150.089 U1.M8@107.677,150.489
  Top Layer w0.254: v1(104.267,144.907) 106.172,143.002 v1(106.172,136.242) ; U2.21@110.241,117.221 v1(111.76,117.221)
  Bottom Layer w0.254: v1(104.267,144.907) 105.029,144.907 107.561,147.439 107.561,148.99 v1(107.277,149.274) ; v1(106.172,136.242) 106.172,122.809 v1(111.76,117.221)
DP: U2.14 USB2.A6 | length 19.6
  Top Layer w0.1: v1@104.779,91.313 USB2.A6@104.779,92.278
  Top Layer w0.254: v1(106.934,105.283) 108.961,107.31 U2.14@108.961,107.836
  Bottom Layer w0.1: v1(104.731,91.313) 104.731,96.503 104.373,96.861 104.373,97.195 104.731,97.553 104.731,103.08 106.405,104.754 106.466,104.754 106.701,104.989 106.701,105.05 v1(106.934,105.283)
FSCL: P1.5 R39.1 U1.A10 | length 27
  Top Layer w0.1: U1.A10@109.277,159.289 109.601,159.613 v1(109.601,159.766) ; v1(114.724,171.788) 114.59,171.922 114.59,173.162 115.062,173.634 R39.1@115.062,173.661 115.634,174.233 P1.5@115.634,175.655
  Bottom Layer w0.1: v1(109.601,159.766) 109.601,160.052 109.52,160.132 109.52,166.923 110.709,168.112 110.709,168.212 110.237,168.684 110.237,168.784 110.42,168.967 110.52,168.967 110.992,168.495 111.092,168.495 111.275,168.678 111.275,168.778 110.803,169.25 110.803,169.35 110.986,169.533 111.086,169.533 111.558,169.061 111.658,169.061 111.841,169.244 111.841,169.344 111.369,169.816 111.369,169.916 111.552,170.099 111.652,170.099 112.124,169.626 112.224,169.626 112.407,169.809 112.407,169.909 111.984,170.331 111.984,170.431 112.167,170.614 112.267,170.614 112.689,170.192 112.789,170.192 112.972,170.375 112.972,170.475 112.55,170.897 112.55,170.997 112.733,171.18 112.833,171.18 113.255,170.758 113.355,170.758 113.561,170.963 113.561,171.063 113.371,171.253 113.371,171.353 113.554,171.536 113.654,171.536 113.844,171.346 113.944,171.346 114.385,171.788 v1(114.724,171.788)
FSDA: P1.3 R38.1 U1.B9 | length 27
  Top Layer w0.1: U1.B9@108.477,158.489 108.839,158.851 v1(108.839,158.877) ; v1(110.363,170.688) 110.819,170.688 R38.1@113.665,173.534 114.115,173.984 114.115,174.12 114.233,174.238 114.369,174.238 114.634,174.503 P1.3@114.634,175.655
  Bottom Layer w0.1: v1(108.839,158.877) 108.839,161.431 108.91,161.502 109.226,161.502 109.297,161.573 109.297,161.831 109.226,161.902 108.91,161.902 108.839,161.973 108.839,162.242 108.91,162.313 109.226,162.313 109.297,162.383 109.297,162.642 109.226,162.713 108.91,162.713 108.839,162.783 108.839,163.042 108.91,163.113 109.226,163.113 109.297,163.183 109.297,163.442 109.226,163.513 108.91,163.513 108.839,163.583 108.839,163.842 108.91,163.913 109.226,163.913 109.297,163.983 109.297,164.242 109.226,164.313 108.91,164.313 108.839,164.383 108.839,164.642 108.91,164.713 109.226,164.713 109.297,164.783 109.297,165.042 109.226,165.113 108.91,165.113 108.839,165.183 108.839,165.442 108.91,165.513 109.226,165.513 109.297,165.583 109.297,165.842 109.226,165.913 108.91,165.913 108.839,165.983 108.839,166.242 108.91,166.313 109.226,166.313 109.297,166.383 109.297,166.642 109.226,166.713 108.91,166.713 108.839,166.783 108.839,167.042 108.91,167.113 109.276,167.113 109.347,167.183 109.347,167.442 109.276,167.513 108.91,167.513 108.839,167.583 108.839,167.842 108.91,167.913 109.276,167.913 109.347,167.983 109.347,168.242 109.276,168.313 108.91,168.313 108.839,168.383 108.839,169.164 v1(110.363,170.688)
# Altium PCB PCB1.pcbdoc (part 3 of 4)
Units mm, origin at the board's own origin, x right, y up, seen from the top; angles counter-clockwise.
Board outline 96.27 x 122.17 mm, 4 copper layers (Top Layer, Inner1, Inner2, Bottom Layer); 135 components, 133 nets, 720 pads, 358 vias.

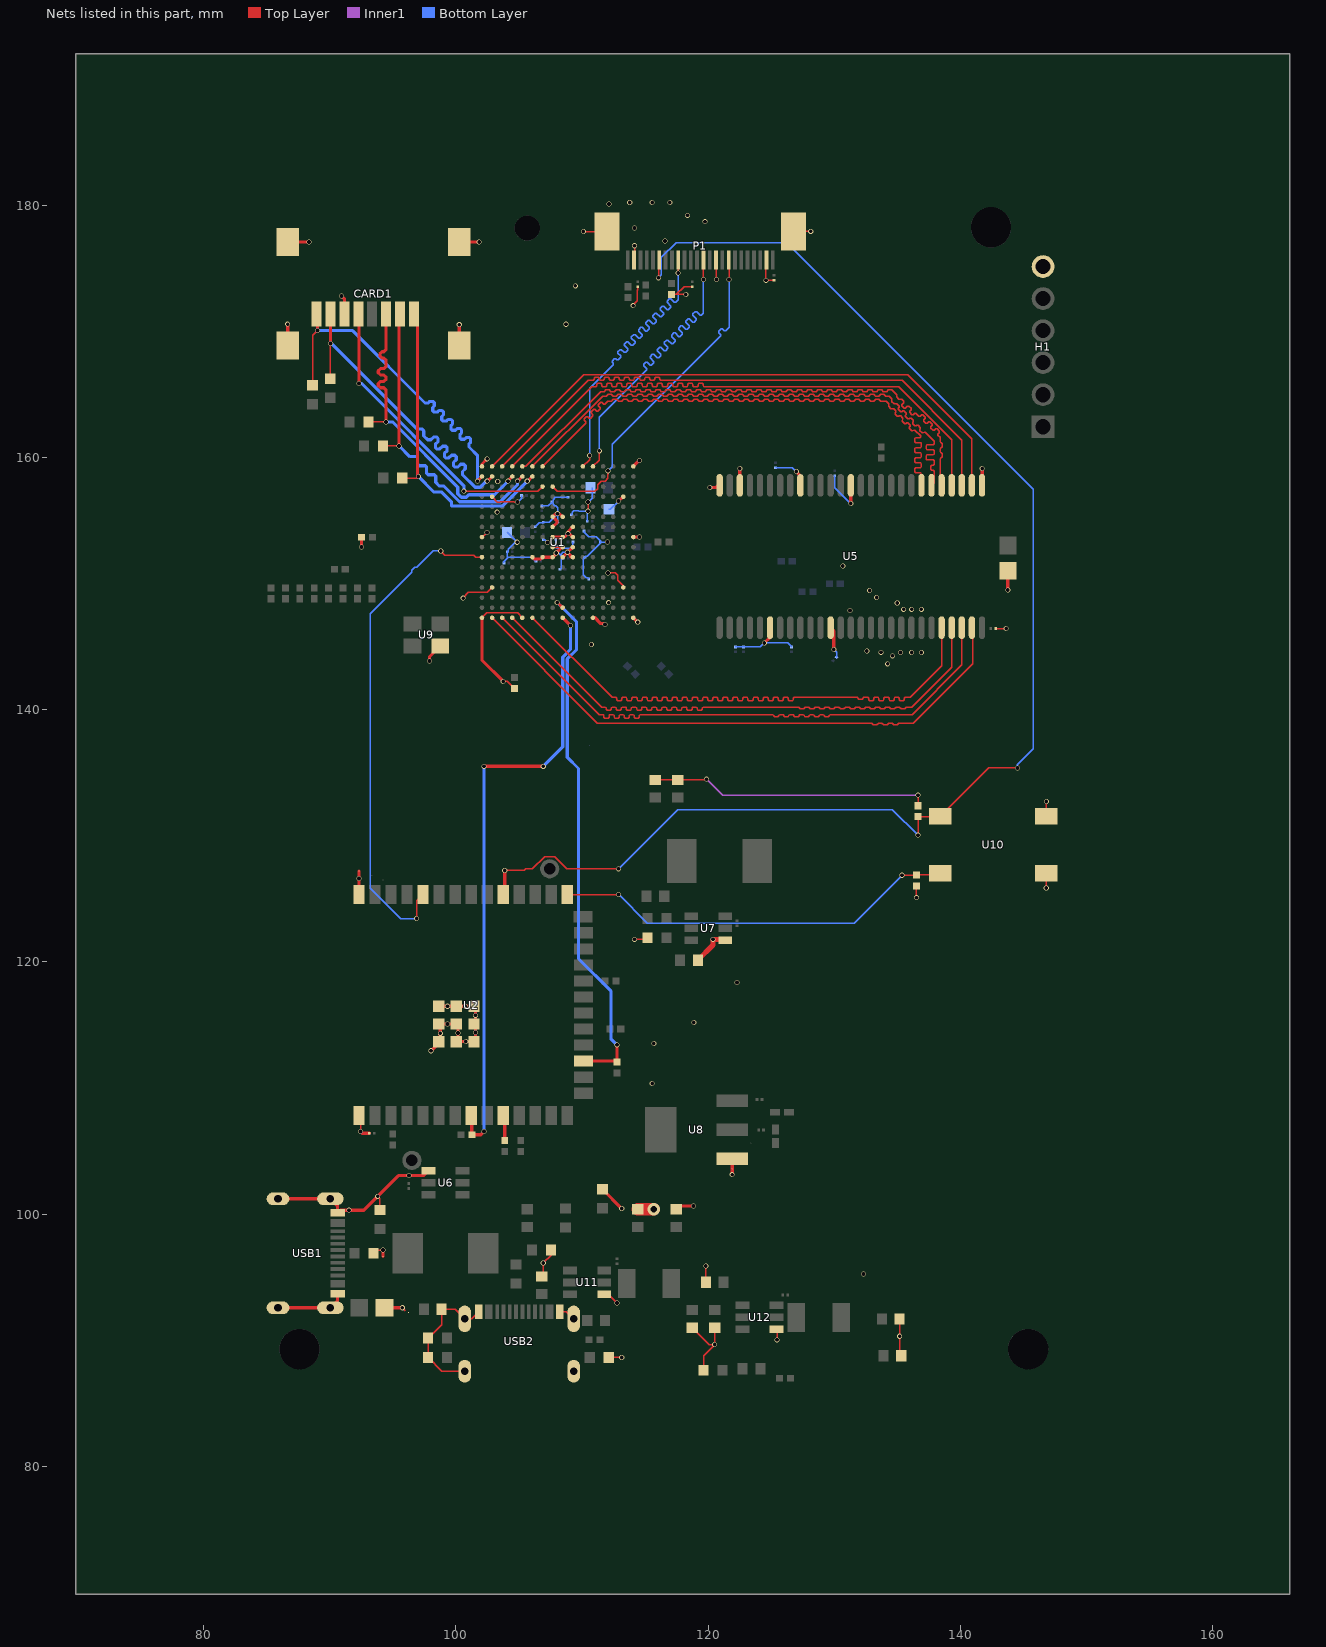
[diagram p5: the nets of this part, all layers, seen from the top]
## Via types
v1: diameter 0.4, hole 0.3, Top Layer to Bottom Layer, 324 vias
v2: diameter 1, hole 0.5, Top Layer to Bottom Layer, 33 vias
v3: diameter 0.5, hole 0.3, Top Layer to Bottom Layer, 1 vias

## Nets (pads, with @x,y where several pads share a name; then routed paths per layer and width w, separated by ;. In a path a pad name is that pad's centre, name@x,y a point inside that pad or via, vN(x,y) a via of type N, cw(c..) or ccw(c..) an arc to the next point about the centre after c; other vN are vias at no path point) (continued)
GND: C8.2 C10.2 C11.2 C12.2 C13.2 C14.2 C15.1 C16.1 C17.1 C20.1 C22.1 C23.1 C26.1 C27.1 C28.1 C33.1 C34.2 C35.2 C37.2 C39.2 C40.2 C41.2 C42.2 C43.2 C44.2 C45.2 C46.2 C47.2 C48.2 C49.2 C50.2 C51.2 C52.2 C53.2 C54.2 C55.2 C56.2 C57.2 C58.2 C59.2 C61.2 C62.2 C63.2 C66.1 C67.1 C68.1 C71.1 C72.1 C73.1 C74.2 CARD1.6 CARD1.9 CARD1.10 CARD1.11 CARD1.12 H1.6 P1.2 P1.15 P1.23 P1.25 P1.26 pad.55@92.324,127.195 pad.55@94.234,96.647 pad.55@96.266,92.202 pad.55@121.914,103.597 R9.1 R10.1 R12.1 R14.1 R24.1 R25.1 R35.2 R36.2 R37.2 R40.1 R42.2 R43.2 R45.1 R46.1 U1.A1 U1.A16 U1.D2 U1.D15 U1.F8 U1.F9 U1.G8 U1.G10 U1.H1 U1.H8 U1.H9 U1.H10 U1.H16 U1.J8 U1.J9 U1.J10 U1.K6 U1.K7 U1.K8 U1.K9 U1.K10 U1.N2 U1.N15 U1.T1 U1.T5 U1.T12 U1.T16 U2.1 U2.40 U2.41 U5.6 U5.12 U5.28 U5.41 U5.46 U5.52 U5.54 U6.4 U7.4 U8.1 U9.2 U10.2 U10.4 U11.4 U12.4 USB1.1 USB1.2 USB1.3 USB1.4 USB1.A1B12 USB1.B1A12 USB2.1 USB2.2 USB2.3 USB2.4 USB2.A1B12 USB2.B1A12 | length 211
  Top Layer w0.1: U2.1@92.324,107.836 92.451,107.709 v1(92.451,106.553) ; R10.1@93.463,96.901 93.717,97.155 v1(94.234,97.155) ; v1(93.804,101.415) 93.98,101.239 R9.1@93.98,100.321 ; v1(95.758,92.583) 96.012,92.329 ; v1(100.584,148.844) 100.584,148.886 101.005,149.307 102.495,149.307 U1.N2@102.877,149.689 ; USB2.3@100.709,87.554 98.891,87.554 R42.2@97.799,88.646 R43.2@97.799,90.17 98.871,91.242 C20.1@98.871,92.456 99.956,92.456 USB2.1@100.709,91.703 101.254,91.703 USB2.A1B12@101.829,92.278 ; U1.T1@102.077,147.289 102.459,147.671 104.895,147.671 U1.T5@105.277,147.289 ; 102.235,153.797 102.477,154.039 v1(102.477,154.051) ; U1.D2@102.877,156.889 103.302,156.464 103.512,156.464 103.519,156.471 104.635,156.471 104.642,156.464 v1@104.902,156.464 ; v1(103.759,142.24) 104.088,142.24 R25.1@104.648,141.68 ; C66.1@106.807,95.061 106.934,95.188 v1(106.934,96.139) 107.56,96.765 R45.1@107.56,97.155 ; U1.J8@107.677,152.889 U1.J9@108.42,152.889 ; USB2.B1A12@108.229,92.278 108.774,92.278 USB2.2@109.349,91.703 ; v1(110.109,177.909) P1.26@111.979,177.909 ; v1(110.477,155.737) 110.49,155.75 v1(110.49,156.464) ; U11.4@111.766,93.637 112.103,93.637 v1(112.776,92.964) ; v1(112.077,150.841) 112.216,150.841 112.246,150.871 112.635,150.871 112.859,150.647 112.859,150.258 113.277,149.84 U1.N15@113.277,149.689 ; R40.1@112.132,88.646 v1(113.157,88.646) ; v1(114.063,172.035) 114.063,172.102 114.39,172.429 114.39,173.245 114.427,173.282 C34.2@114.427,173.541 ; P1.2@114.135,175.655 114.173,175.694 v1(114.173,176.784) ; v1(114.173,121.793) 115.071,121.793 R14.1@115.198,121.92 ; C27.1@115.824,134.431 C28.1@117.602,134.431 119.826,134.431 v1(119.888,134.493) ; R35.2@117.094,172.922 117.491,172.922 ; v1(118.237,172.922) 117.491,172.922 ; C68.1@118.745,90.994 120.077,89.662 v1(120.523,89.662) ; C35.2@118.745,173.541 118.11,173.541 117.491,172.922 ; R46.1@119.643,87.63 119.643,88.782 v1(120.523,89.662) ; C71.1@119.823,94.615 v1(119.823,95.885) ; C67.1@120.523,90.994 v1(120.523,89.662) ; P1.15@120.631,175.654 120.667,175.617 120.667,174.455 120.65,174.437 v1@120.65,174.117 ; P1.23@124.636,175.652 124.587,175.603 v1(124.587,174.045) 124.591,174.049 C74.2@125.222,174.049 ; U12.4@125.429,90.871 125.476,90.824 v1(125.476,90.043) ; P1.25@126.781,177.916 128.132,177.916 v1(128.143,177.927) ; C73.1@135.193,91.694 v1(135.193,90.323) 135.193,88.9 C72.1@135.32,88.773 ; v1(136.525,125.095) R37.2@136.525,126.036 ; R36.2@136.652,132.386 v1(136.652,133.223) ; C14.2@142.816,146.431 v1(143.637,146.431) ; v1(146.812,125.857) 146.821,125.866 U10.4@146.821,127.036 ; U10.2@146.821,131.536 v1(146.821,132.715)
  Top Layer w0.254: USB1.4@85.903,92.581 USB1.2@90.052,92.581 90.627,93.156 USB1.B1A12@90.627,93.701 ; USB1.3@85.903,101.221 USB1.1@90.052,101.221 90.627,100.646 USB1.A1B12@90.627,100.101 90.848,100.321 v1(91.526,100.321) 92.71,100.321 v1(93.804,101.415) 95.447,103.058 v1(96.299,103.058) 97.161,103.058 97.171,103.068 97.466,103.068 U6.4@97.837,103.439 ; CARD1.10@86.672,168.874 v1(86.672,170.565) ; CARD1.9@86.672,177.074 v1(88.357,177.074) ; v1(90.945,172.801) 91.172,172.574 CARD1.6@91.172,171.374 ; pad.55@92.324,127.195 v1(92.324,126.623) 92.324,125.463 U2.40@92.451,125.336 ; v1(92.451,106.553) 92.578,106.426 C17.1@93.15,106.426 ; v1(92.531,152.902) R24.1@92.531,153.67 ; pad.55@94.234,96.647 v1(94.234,97.155) ; C33.1@94.345,92.583 v1(95.758,92.583) ; v1(97.917,143.861) 97.917,144.202 U9.2@98.763,145.048 ; v1(98.045,112.96) 98.771,113.686 v1(98.771,114.339) 98.771,115.086 v1(99.347,115.086) 100.171,115.086 v1(100.171,114.364) 100.171,113.686 v1(100.791,113.686) 101.571,113.686 v1(101.571,114.408) v1(101.571,115.77) 101.571,116.486 v1(100.722,116.486) U2.41@100.044,116.486 v1(99.347,116.486) U2.41@98.771,116.486 ; CARD1.11@100.272,168.874 v1(100.272,170.523) ; CARD1.12@100.272,177.074 v1(101.854,177.074) ; U1.T1@102.077,147.289 102.077,143.922 v1(103.759,142.24) ; U1.A1@102.077,159.289 102.077,159.481 v1(102.489,159.893) ; U1.K6@106.077,152.089 106.218,151.948 106.736,151.948 U1.K7@106.877,152.089 U1.K8@107.677,152.089 107.964,152.376 v1(107.964,152.432) 108.42,152.889 U1.J9@108.477,152.889 ; U1.H8@107.677,153.689 U1.H9@108.477,153.689 108.628,153.689 v1(108.896,153.957) ; U1.G8@107.677,154.489 108.029,154.841 108.029,154.937 U1.F8@107.677,155.289 107.931,155.543 v1(108.068,155.543) 108.223,155.543 U1.F9@108.477,155.289 ; U1.K9@108.477,152.089 108.856,152.468 v1(108.856,152.481) ; U1.K10@109.121,152.117 109.121,152.215 v1(108.856,152.481) ; U1.J10@109.277,152.889 109.264,152.889 v1(108.856,152.481) ; U1.H10@109.277,153.689 109.009,153.957 v1(108.896,153.957) ; U1.G10@109.277,154.489 108.896,154.108 v1(108.896,153.957) ; U1.T12@110.877,147.289 111.064,147.289 111.218,147.135 111.218,147.099 111.487,146.83 111.747,146.83 v1(111.82,146.757) ; R12.1@111.633,101.972 v1(113.157,100.448) ; v1@112.903,156.591 112.979,156.591 U1.D15@113.277,156.889 ; U1.T16@114.077,147.289 v1(114.427,146.939) ; U1.H16@114.077,153.689 v1(114.554,153.691) ; U1.A16@114.077,159.289 v1(114.554,159.766) ; C22.1@117.475,100.395 117.726,100.646 v1(118.846,100.646) ; v1(120.142,157.607) 120.61,157.607 U5.54@120.918,157.915 ; v1(121.914,103.134) pad.55@121.914,103.597 U8.1@121.914,104.409 ; U5.52@122.518,157.915 v1(122.518,159.131) ; v1(124.46,145.288) 124.918,145.746 U5.6@124.918,146.504 ; v1(127,158.877) 127.318,158.559 U5.46@127.318,157.788 ; U5.12@129.718,146.504 129.972,146.25 v1(129.972,144.78) ; v1(131.318,156.337) U5.41@131.318,157.915 ; U5.28@141.718,157.788 141.732,157.802 v1(141.732,159.131) ; v1(143.764,149.479) C8.2@143.764,151.019
  Top Layer w0.4: C26.1@119.191,120.142 120.396,121.347 v1(120.396,121.793) 121.304,121.793 U7.4@121.365,121.732
  Top Layer w1: C23.1@114.427,100.395 v2(115.689,100.395)
  Inner1 w0.1: v1(119.888,134.493) 121.158,133.223 v1(136.652,133.223)
  Bottom Layer w0.1: C51.2@103.818,151.638 103.818,151.749 104.072,152.003 ; C61.2@104.075,154.051 104.089,154.051 v1(104.864,153.276) 104.711,153.276 104.155,152.721 104.155,152.567 104.115,152.527 C56.2@104.072,152.527 104.072,152.003 ; v1(104.901,156.465) 105.215,156.779 C37.2@105.215,156.972 ; C41.2@106.299,154.5 106.612,154.813 106.875,154.813 C62.2@106.934,154.872 107.397,154.872 v1(108.068,155.543) ; C54.2@106.358,151.765 106.032,152.091 104.16,152.091 104.072,152.003 ; C63.2@106.807,156.151 107.315,156.151 C50.2@107.628,156.464 ; C45.2@106.934,153.475 107.043,153.475 v1(107.263,153.256) ; C46.2@107.882,153.543 107.935,153.49 107.935,152.991 C57.2@108.018,152.908 108.113,152.813 109.188,152.813 ; v1(107.964,152.432) 108.103,152.432 108.346,152.19 ; C42.2@108.068,154.826 v1(108.068,155.543) ; C53.2@108.263,151.13 108.346,151.213 108.346,151.919 108.446,152.019 C49.2@108.517,152.019 108.346,152.19 ; C39.2@108.898,156.845 107.898,156.845 107.711,156.658 107.711,156.547 C50.2@107.628,156.464 ; C43.2@109.152,155.448 109.235,155.531 109.235,155.642 109.353,155.76 109.731,155.76 109.754,155.737 v1(110.477,155.737) 110.422,155.682 C40.2@110.422,154.94 ; C47.2@109.288,153.289 109.288,152.913 109.188,152.813 ; C44.2@110.168,154.178 110.168,154.067 110.534,153.701 111.146,153.701 111.447,153.4 C55.2@111.447,153.289 ; v1(110.49,156.464) 110.806,156.78 C58.2@110.806,157.607 ; C48.2@110.549,150.368 110.443,150.474 110.323,150.474 110.088,150.709 110.088,151.93 C52.2@110.236,152.078 110.319,152.161 110.43,152.161 111.447,153.178 C55.2@111.447,153.289 ; v1@112.014,153.289 C55.2@111.447,153.289 ; C59.2@112.141,155.894 112.254,155.894 v1(112.903,156.544) ; C10.2@122.174,144.975 C11.2@122.809,144.975 124.147,144.975 v1(124.46,145.288) 126.306,145.288 C12.2@126.619,144.975 ; C16.1@125.349,159.19 126.687,159.19 v1(127,158.877) ; v1(129.972,144.78) 130.186,144.566 C13.2@130.186,144.156 ; C15.1@130.048,158.555 130.048,157.607 v1(131.318,156.337) ; C50.2@107.628,156.464 107.711,156.381 107.711,156.27 107.829,156.152 107.94,156.152 108.068,156.024 v1(108.068,155.543) ; 108.346,152.19 108.346,152.331 108.496,152.481 v1(108.856,152.481) 109.188,152.813
  other v1: 132.334,95.25 115.57,110.363 115.697,113.538 118.872,115.189 122.301,118.364 134.239,143.637 134.62,144.272 135.255,144.526 136.144,144.526 136.906,144.526 133.707,144.55 132.588,144.653 110.744,145.161 131.261,147.864 135.509,147.955 136.144,147.955 136.906,147.955 135.001,148.463 112.121,148.485 133.372,148.884 132.812,149.449 130.683,151.384 112.029,153.289 103.279,155.659 103.326,158.088 108.733,170.561 109.474,173.609 120.667,174.117 116.586,177.165 114.173,178.181 119.761,178.689 118.364,179.197 112.141,180.086 113.792,180.213 115.57,180.213 116.967,180.213
HREF: P1.9 U1.A11 | length 27
  Top Layer w0.1: U1.A11@110.077,159.289 110.617,159.829 v1(110.617,160.147) ; v1(117.634,174.625) P1.9@117.634,175.655
  Bottom Layer w0.1: v1(110.617,160.147) 110.617,165.481 112.485,167.349 112.485,167.449 112.395,167.54 112.395,167.64 112.578,167.823 112.678,167.823 112.768,167.732 112.868,167.732 113.079,167.943 113.079,168.043 112.848,168.274 112.848,168.374 113.031,168.557 113.131,168.557 113.362,168.326 113.462,168.326 113.645,168.509 113.645,168.609 113.364,168.89 113.364,168.99 113.547,169.173 113.647,169.173 113.928,168.892 114.028,168.892 114.211,169.075 114.211,169.175 113.93,169.456 113.93,169.556 114.113,169.739 114.213,169.739 114.494,169.458 114.594,169.458 114.776,169.64 114.776,169.74 114.495,170.021 114.495,170.121 114.678,170.304 114.778,170.304 115.059,170.023 115.159,170.023 115.342,170.206 115.342,170.306 115.061,170.587 115.061,170.687 115.244,170.87 115.344,170.87 115.625,170.589 115.725,170.589 115.908,170.772 115.908,170.872 115.627,171.153 115.627,171.253 115.81,171.436 115.91,171.436 116.191,171.155 116.291,171.155 116.474,171.338 116.474,171.438 116.193,171.719 116.193,171.819 116.375,172.001 116.475,172.001 116.756,171.72 116.856,171.72 117.039,171.903 117.039,172.003 116.758,172.284 116.758,172.384 116.941,172.567 117.041,172.567 117.322,172.286 117.422,172.286 117.634,172.498 v1(117.634,174.625)
INITN: pad.55@102.235,127.254 R5.1 U1.T9 U2.8 | length 49.2
  Top Layer w0.254: U2.8@101.341,107.836 101.271,107.766 R5.1@101.271,106.299 101.981,106.299 v1(102.235,106.553) ; v1(102.235,135.509) v1(106.934,135.509) ; U1.T9@108.477,147.289 109.081,146.685 v1(109.093,146.685)
  Bottom Layer w0.254: v1(102.235,106.553) pad.55@102.235,127.254 v1(102.235,135.509) ; v1(106.934,135.509) 108.485,137.06 108.485,144.172 109.093,144.78 v1(109.093,146.685)
M_CLK: CARD1.5 U1.C7 | length 24
  Top Layer w0.1: v1(100.639,157.325) 100.656,157.307 106.495,157.307 U1.C7@106.877,157.689
  Top Layer w0.254: CARD1.5@92.272,171.374 92.329,171.317 v1(92.329,165.862)
  Bottom Layer w0.254: v1(92.329,165.862) 92.541,165.862 100.639,157.764 v1(100.639,157.325)
M_CMD: CARD1.3 R20.1 U1.B4 | length 25.6
  Top Layer w0.1: R20.1@93.082,162.814 v1(94.472,162.814)
  Top Layer w0.254: v1(94.472,162.814) 94.472,165.339 94.293,165.518 94.033,165.518 93.853,165.698 93.853,165.847 94.033,166.026 94.293,166.026 94.472,166.206 94.472,166.355 94.293,166.534 94.033,166.534 93.853,166.714 93.853,166.863 94.033,167.042 94.293,167.042 94.472,167.222 94.472,167.699 94.293,167.878 94.16,167.878 93.98,168.058 93.98,168.207 94.16,168.386 94.293,168.386 94.472,168.566 CARD1.3@94.472,171.374 ; v1(104.14,158.115) 104.14,158.152 U1.B4@104.477,158.489
  Bottom Layer w0.254: v1(94.472,162.814) 94.98,162.814 100.16,157.634 100.16,157.126 100.44,156.846 100.837,156.846 101.036,157.045 103.07,157.045 v1(104.14,158.115)
M_D0: CARD1.7 R18.1 U1.B2 | length 26.9
  Top Layer w0.1: R18.1@90.043,166.234 90.043,169.008 v1(90.072,169.037)
  Top Layer w0.254: v1(90.072,169.037) CARD1.7@90.072,171.374 ; v1(102.489,158.115) 102.503,158.115 U1.B2@102.877,158.489
  Bottom Layer w0.254: v1(90.072,169.037) 90.128,169.037 96.902,162.263 97.304,162.263 97.462,162.104 97.462,161.703 97.766,161.398 98.02,161.398 98.232,161.61 98.486,161.61 98.591,161.505 98.591,161.251 98.38,161.039 98.38,160.785 98.485,160.68 98.739,160.68 98.95,160.892 99.204,160.892 99.31,160.786 99.31,160.532 99.098,160.321 99.098,160.067 99.203,159.961 99.457,159.961 99.669,160.173 99.923,160.173 100.028,160.068 100.028,159.814 99.816,159.602 99.816,159.348 99.922,159.243 100.176,159.243 100.387,159.455 100.641,159.455 100.747,159.349 100.747,159.095 100.535,158.884 100.535,158.63 101.529,157.636 101.925,157.636 102.404,158.115 v1(102.489,158.115)
M_D1: CARD1.8 R19.1 U1.B1 | length 28.5
  Top Layer w0.1: R19.1@88.646,165.726 88.646,169.672 v1(89.027,170.053)
  Top Layer w0.254: CARD1.8@88.972,171.374 89.027,171.319 v1(89.027,170.053) ; v1(101.727,158.115) 101.727,158.139 U1.B1@102.077,158.489
  Bottom Layer w0.254: v1(89.027,170.053) 91.821,170.053 97.558,164.316 97.812,164.316 97.939,164.443 98.193,164.443 98.298,164.338 98.298,164.084 98.171,163.957 98.171,163.703 98.277,163.597 98.531,163.597 98.658,163.724 98.912,163.724 99.017,163.619 99.017,163.365 98.89,163.238 98.89,162.984 98.995,162.879 99.249,162.879 99.376,163.006 99.63,163.006 99.735,162.901 99.735,162.647 99.608,162.52 99.608,162.266 99.714,162.16 99.968,162.16 100.095,162.287 100.349,162.287 100.454,162.182 100.454,161.928 100.327,161.801 100.327,161.547 100.432,161.442 100.686,161.442 100.813,161.569 101.067,161.569 101.172,161.464 101.172,161.21 101.045,161.083 101.045,160.829 101.727,160.147 v1(101.727,158.115)
M_D2: CARD1.1 R16.1 U1.B6 | length 25.4
  Top Layer w0.1: R16.1@95.876,158.369 96.901,158.369 v1(97.028,158.496)
  Top Layer w0.254: CARD1.1@96.672,171.374 96.957,171.089 96.957,158.567 v1(97.028,158.496) ; v1(105.664,158.115) 105.703,158.115 U1.B6@106.077,158.489
  Bottom Layer w0.254: v1(97.028,158.496) 98.269,157.255 98.895,157.255 99.653,156.497 99.653,156.138 103.687,156.138 v1(105.664,158.115)
M_D3: CARD1.2 R17.1 U1.B5 | length 25.2
  Top Layer w0.1: R17.1@94.225,160.909 v1(95.504,160.909)
  Top Layer w0.254: v1(95.504,160.909) 95.504,171.306 CARD1.2@95.572,171.374 ; v1(104.902,158.115) U1.B5@105.277,158.489
  Bottom Layer w0.254: v1(95.504,160.909) 95.517,160.909 96.362,160.064 96.857,160.064 96.969,159.952 96.969,159.457 97.081,159.346 97.575,159.346 97.687,159.234 97.687,158.739 97.799,158.627 98.294,158.627 98.406,158.515 98.406,158.021 98.692,157.734 99.051,157.734 100.294,156.492 103.54,156.492 104.902,157.854 v1(104.902,158.115)
MCLK: P1.13 U1.A12 | length 27.1
  Top Layer w0.1: U1.A12@110.877,159.289 111.379,159.791 v1(111.379,160.528) ; v1(119.634,174.117) P1.13@119.634,175.655
  Bottom Layer w0.1: v1(111.379,160.528) 111.379,163.195 115.124,166.94 115.124,167.04 114.893,167.271 114.893,167.371 115.076,167.554 115.176,167.554 115.407,167.323 115.507,167.323 115.69,167.506 115.69,167.606 115.409,167.887 115.409,167.987 115.592,168.17 115.692,168.17 115.973,167.889 116.073,167.889 116.255,168.071 116.255,168.171 115.974,168.452 115.974,168.552 116.157,168.735 116.257,168.735 116.538,168.454 116.638,168.454 116.821,168.637 116.821,168.737 116.54,169.018 116.54,169.118 116.723,169.301 116.823,169.301 117.104,169.02 117.204,169.02 117.387,169.203 117.387,169.303 117.106,169.584 117.106,169.684 117.289,169.867 117.389,169.867 117.67,169.586 117.77,169.586 117.952,169.768 117.952,169.868 117.671,170.149 117.671,170.249 117.854,170.432 117.954,170.432 118.235,170.151 118.335,170.151 118.518,170.334 118.518,170.434 118.237,170.715 118.237,170.815 118.42,170.998 118.52,170.998 118.801,170.717 118.901,170.717 119.084,170.9 119.084,171 118.803,171.281 118.803,171.381 118.986,171.564 119.086,171.564 119.367,171.283 119.467,171.283 119.634,171.45 v1(119.634,174.117)
PCLK: P1.17 U1.C8 | length 27
  Top Layer w0.1: U1.C8@107.677,157.689 108.059,157.307 111.035,157.307 111.259,157.531 111.259,157.847 111.519,158.107 111.835,158.107 112.059,158.331 112.059,158.647 112.077,158.665 v1(112.077,158.937) ; P1.17@121.634,175.656 121.666,175.624 v1(121.666,174.117)
  Bottom Layer w0.1: v1(112.077,158.937) 112.416,159.276 112.416,161.057 121.006,169.647 121.006,169.747 120.852,169.901 120.852,170.001 121.034,170.183 121.134,170.183 121.288,170.029 121.388,170.029 121.666,170.307 v1(121.666,174.117)
PROGRAM: R37.1 U2.27 U10.3 | length 32.2
  Top Layer w0.1: U2.27@108.834,125.336 112.89,125.336 v1(112.903,125.349) ; v1(135.382,126.873) 136.497,126.873 R37.1@136.525,126.901 138.287,126.901 U10.3@138.421,127.036
  Bottom Layer w0.1: v1(112.903,125.349) 115.189,123.063 131.572,123.063 v1(135.382,126.873)
PROGRAMN: pad.55@108.839,136.377 R4.2 U1.R9 U2.17 | length 42.2
  Top Layer w0.254: v1(108.04,148.5) 108.066,148.5 U1.R9@108.477,148.089 ; U2.17@110.241,112.141 112.701,112.141 R4.2@112.776,112.066 v1(112.776,113.428)
  Bottom Layer w0.254: v1(108.04,148.5) 109.572,146.968 109.572,144.758 108.839,144.025 pad.55@108.839,136.377 108.839,136.229 109.728,135.34 109.728,120.269 112.297,117.7 112.297,113.907 v1(112.776,113.428)
RESET: P1.6 R36.1 U2.31 U10.1 | length 113.1
  Top Layer w0.1: v1(103.881,127.254) 105.41,127.254 105.537,127.381 106.079,127.381 107.043,128.345 107.841,128.345 108.805,127.381 v1(112.903,127.381) ; v1(116.078,174.244) 116.078,175.599 P1.6@116.135,175.655 ; v1(136.652,130.048) R36.1@136.652,131.52 138.405,131.52 U10.1@138.421,131.536 142.267,135.382 v1(144.526,135.382)
  Top Layer w0.254: U2.31@103.881,125.336 v1(103.881,127.254)
  Bottom Layer w0.1: v1(112.903,127.381) 117.602,132.08 134.62,132.08 v1(136.652,130.048) ; v1(116.078,174.244) 116.304,174.47 116.304,175.867 117.475,177.038 126.238,177.038 145.796,157.48 145.796,136.906 144.526,135.636 v1(144.526,135.382)
RX: U1.K1 U2.36 | length 39.7
  Top Layer w0.1: v1(96.901,123.444) 96.901,124.833 U2.36@97.404,125.336 ; v1(98.807,152.582) 99.135,152.254 101.434,152.254 101.599,152.089 U1.K1@102.077,152.089
  Bottom Layer w0.1: v1(96.901,123.444) 95.631,123.444 93.218,125.857 93.218,147.598 96.499,150.879 96.499,151.043 96.734,151.278 96.898,151.278 98.202,152.582 v1(98.807,152.582)
SCL: R21.1 U2.10 | length 1.9
  Top Layer w0.254: U2.10@103.881,107.836 103.886,107.831 R21.1@103.886,105.918
SD_A0: U1.T6 U5.23 | length 46.8
  Top Layer w0.1: U1.T6@106.077,147.289 112.396,140.97 112.696,140.97 112.767,140.899 112.767,140.787 112.837,140.716 113.096,140.716 113.167,140.787 113.167,140.899 113.237,140.97 113.496,140.97 113.567,140.899 113.567,140.787 113.637,140.716 113.896,140.716 113.967,140.787 113.967,140.899 114.037,140.97 114.296,140.97 114.367,140.899 114.367,140.787 114.437,140.716 114.696,140.716 114.767,140.787 114.767,140.899 114.837,140.97 115.096,140.97 115.167,140.899 115.167,140.787 115.237,140.716 115.496,140.716 115.567,140.787 115.567,140.899 115.637,140.97 115.896,140.97 115.967,140.899 115.967,140.787 116.037,140.716 116.296,140.716 116.367,140.787 116.367,140.899 116.437,140.97 116.696,140.97 116.767,140.899 116.767,140.787 116.837,140.716 117.096,140.716 117.167,140.787 117.167,140.899 117.237,140.97 117.496,140.97 117.567,140.899 117.567,140.787 117.637,140.716 117.896,140.716 117.967,140.787 117.967,140.899 118.037,140.97 118.296,140.97 118.367,140.899 118.367,140.787 118.437,140.716 118.696,140.716 118.767,140.787 118.767,140.899 118.837,140.97 119.096,140.97 119.167,140.899 119.167,140.787 119.237,140.716 119.496,140.716 119.567,140.787 119.567,140.899 119.637,140.97 119.896,140.97 119.967,140.899 119.967,140.787 120.037,140.716 120.296,140.716 120.367,140.787 120.367,140.899 120.437,140.97 120.696,140.97 120.767,140.899 120.767,140.787 120.837,140.716 121.096,140.716 121.167,140.787 121.167,140.899 121.237,140.97 121.496,140.97 121.567,140.899 121.567,140.787 121.637,140.716 121.896,140.716 121.967,140.787 121.967,140.899 122.037,140.97 122.296,140.97 122.367,140.899 122.367,140.787 122.437,140.716 122.696,140.716 122.767,140.787 122.767,140.899 122.837,140.97 123.096,140.97 123.167,140.899 123.167,140.787 123.237,140.716 123.496,140.716 123.567,140.787 123.567,140.899 123.637,140.97 123.896,140.97 123.967,140.899 123.967,140.787 124.037,140.716 124.296,140.716 124.367,140.787 124.367,140.899 124.437,140.97 124.696,140.97 124.767,140.899 124.767,140.787 124.837,140.716 125.096,140.716 125.167,140.787 125.167,140.899 125.237,140.97 125.496,140.97 125.567,140.899 125.567,140.787 125.637,140.716 125.896,140.716 125.967,140.787 125.967,140.899 126.037,140.97 126.296,140.97 126.367,140.899 126.367,140.787 126.437,140.716 126.696,140.716 126.767,140.787 126.767,140.899 126.837,140.97 131.82,140.97 131.947,140.843 132.22,140.843 132.347,140.97 132.678,140.97 132.748,140.899 132.748,140.787 132.819,140.716 133.078,140.716 133.148,140.787 133.148,140.899 133.219,140.97 133.478,140.97 133.548,140.899 133.548,140.787 133.619,140.716 133.878,140.716 133.948,140.787 133.948,140.899 134.019,140.97 134.278,140.97 134.348,140.899 134.348,140.787 134.419,140.716 134.678,140.716 134.748,140.787 134.748,140.899 134.819,140.97 135.078,140.97 135.148,140.899 135.148,140.787 135.219,140.716 135.478,140.716 135.548,140.787 135.548,140.899 135.619,140.97 136.017,140.97 138.518,143.471 U5.23@138.518,146.504
SD_A1: U1.T4 U5.24 | length 46.8
  Top Layer w0.1: U1.T4@104.477,147.289 111.558,140.208 111.858,140.208 111.929,140.137 111.929,140.025 111.999,139.954 112.258,139.954 112.329,140.025 112.329,140.137 112.399,140.208 112.658,140.208 112.729,140.137 112.729,140.025 112.799,139.954 113.058,139.954 113.129,140.025 113.129,140.137 113.199,140.208 113.458,140.208 113.529,140.137 113.529,140.025 113.599,139.954 113.858,139.954 113.929,140.025 113.929,140.137 113.999,140.208 114.258,140.208 114.329,140.137 114.329,140.025 114.399,139.954 114.658,139.954 114.729,140.025 114.729,140.137 114.799,140.208 115.058,140.208 115.129,140.137 115.129,140.025 115.199,139.954 115.458,139.954 115.529,140.025 115.529,140.137 115.599,140.208 115.858,140.208 115.929,140.137 115.929,140.025 115.999,139.954 116.258,139.954 116.329,140.025 116.329,140.137 116.399,140.208 116.658,140.208 116.729,140.137 116.729,140.025 116.799,139.954 117.058,139.954 117.129,140.025 117.129,140.137 117.199,140.208 117.458,140.208 117.529,140.137 117.529,140.025 117.599,139.954 117.858,139.954 117.929,140.025 117.929,140.137 117.999,140.208 118.258,140.208 118.329,140.137 118.329,140.025 118.399,139.954 118.658,139.954 118.729,140.025 118.729,140.137 118.799,140.208 119.058,140.208 119.129,140.137 119.129,140.025 119.199,139.954 119.458,139.954 119.529,140.025 119.529,140.137 119.599,140.208 127.177,140.208 127.304,140.081 127.577,140.081 127.704,140.208 127.977,140.208 128.104,140.081 128.377,140.081 128.504,140.208 128.777,140.208 128.904,140.081 129.177,140.081 129.304,140.208 129.577,140.208 129.704,140.081 129.977,140.081 130.104,140.208 130.377,140.208 130.504,140.081 130.777,140.081 130.904,140.208 131.177,140.208 131.304,140.081 131.577,140.081 131.704,140.208 131.977,140.208 132.104,140.081 132.377,140.081 132.504,140.208 132.777,140.208 132.904,140.081 133.177,140.081 133.304,140.208 133.577,140.208 133.704,140.081 133.977,140.081 134.104,140.208 134.377,140.208 134.504,140.081 134.777,140.081 134.904,140.208 135.177,140.208 135.304,140.081 135.577,140.081 135.704,140.208 136.144,140.208 139.319,143.383 U5.24@139.319,146.503
SD_A2: U1.T3 U5.25 | length 46.9
  Top Layer w0.1: U1.T3@103.677,147.289 111.356,139.61 111.679,139.61 111.75,139.539 111.75,139.39 111.82,139.319 112.079,139.319 112.15,139.39 112.15,139.539 112.22,139.61 112.479,139.61 112.55,139.539 112.55,139.39 112.62,139.319 112.879,139.319 112.95,139.39 112.95,139.539 113.02,139.61 113.279,139.61 113.35,139.539 113.35,139.39 113.42,139.319 113.679,139.319 113.75,139.39 113.75,139.539 113.82,139.61 114.079,139.61 114.15,139.539 114.15,139.39 114.22,139.319 114.479,139.319 114.55,139.39 114.55,139.539 114.62,139.61 125.143,139.61 125.214,139.539 125.214,139.517 125.285,139.446 125.543,139.446 125.614,139.517 125.614,139.539 125.685,139.61 125.943,139.61 126.014,139.539 126.014,139.517 126.085,139.446 126.343,139.446 126.414,139.517 126.414,139.539 126.485,139.61 126.743,139.61 126.814,139.539 126.814,139.517 126.885,139.446 127.143,139.446 127.214,139.517 127.214,139.539 127.285,139.61 127.543,139.61 127.614,139.539 127.614,139.517 127.685,139.446 127.943,139.446 128.014,139.517 128.014,139.539 128.085,139.61 128.343,139.61 128.414,139.539 128.414,139.517 128.485,139.446 128.743,139.446 128.814,139.517 128.814,139.539 128.885,139.61 129.143,139.61 129.214,139.539 129.214,139.517 129.285,139.446 129.543,139.446 129.614,139.517 129.614,139.539 129.685,139.61 136.181,139.61 140.118,143.547 U5.25@140.118,146.504
SD_A3: U1.T2 U5.26 | length 46.7
  Top Layer w0.1: U1.T2@102.877,147.289 111.228,138.938 132.99,138.938 133.117,138.811 133.39,138.811 133.517,138.938 133.79,138.938 133.917,138.811 134.19,138.811 134.317,138.938 134.59,138.938 134.717,138.811 134.99,138.811 135.117,138.938 136.271,138.938 140.97,143.637 140.97,146.452 U5.26@140.918,146.504
SD_A4: U1.A2 U5.29 | length 46.9
  Top Layer w0.1: U1.A2@102.877,159.289 110.158,166.57 135.817,166.57 140.918,161.469 U5.29@140.918,157.788
SD_A5: U1.A3 U5.30 | length 46.8
  Top Layer w0.1: U1.A3@103.677,159.289 110.504,166.116 110.896,166.116 110.967,166.187 110.967,166.27 111.038,166.341 111.296,166.341 111.367,166.27 111.367,166.187 111.438,166.116 111.696,166.116 111.767,166.187 111.767,166.27 111.838,166.341 112.096,166.341 112.167,166.27 112.167,166.187 112.238,166.116 112.496,166.116 112.567,166.187 112.567,166.27 112.638,166.341 112.896,166.341 112.967,166.27 112.967,166.187 113.038,166.116 113.296,166.116 113.367,166.187 113.367,166.27 113.438,166.341 113.696,166.341 113.767,166.27 113.767,166.187 113.838,166.116 114.096,166.116 114.167,166.187 114.167,166.27 114.238,166.341 114.496,166.341 114.567,166.27 114.567,166.187 114.638,166.116 114.896,166.116 114.967,166.187 114.967,166.27 115.038,166.341 115.296,166.341 115.367,166.27 115.367,166.187 115.438,166.116 115.696,166.116 115.767,166.187 115.767,166.27 115.838,166.341 116.096,166.341 116.167,166.27 116.167,166.187 116.238,166.116 135.382,166.116 140.118,161.38 U5.30@140.118,157.788
SD_A6: U1.A4 U5.31 | length 46.7
  Top Layer w0.1: U1.A4@104.477,159.289 110.796,165.608 111.096,165.608 111.167,165.679 111.167,165.791 111.237,165.862 111.496,165.862 111.567,165.791 111.567,165.679 111.637,165.608 111.896,165.608 111.967,165.679 111.967,165.791 112.037,165.862 112.296,165.862 112.367,165.791 112.367,165.679 112.437,165.608 112.696,165.608 112.767,165.679 112.767,165.791 112.837,165.862 113.096,165.862 113.167,165.791 113.167,165.679 113.237,165.608 113.496,165.608 113.567,165.679 113.567,165.791 113.637,165.862 113.896,165.862 113.967,165.791 113.967,165.679 114.037,165.608 114.296,165.608 114.367,165.679 114.367,165.791 114.437,165.862 114.696,165.862 114.767,165.791 114.767,165.679 114.837,165.608 115.096,165.608 115.167,165.679 115.167,165.791 115.237,165.862 115.496,165.862 115.567,165.791 115.567,165.679 115.637,165.608 115.896,165.608 115.967,165.679 115.967,165.791 116.037,165.862 116.296,165.862 116.367,165.791 116.367,165.679 116.437,165.608 116.732,165.608 116.803,165.679 116.803,165.809 116.874,165.879 117.132,165.879 117.203,165.809 117.203,165.679 117.274,165.608 117.532,165.608 117.603,165.679 117.603,165.809 117.674,165.879 117.932,165.879 118.003,165.809 118.003,165.679 118.074,165.608 118.332,165.608 118.403,165.679 118.403,165.809 118.474,165.879 118.732,165.879 118.803,165.809 118.803,165.679 118.874,165.608 119.132,165.608 119.203,165.679 119.203,165.809 119.274,165.879 119.532,165.879 119.603,165.809 119.603,165.679 119.674,165.608 135.128,165.608 139.318,161.418 U5.31@139.318,157.788
SD_A7: U1.A5 U5.32 | length 46.8
  Top Layer w0.1: U1.A5@105.277,159.289 105.537,159.289 111.475,165.227 111.775,165.227 111.902,165.354 112.175,165.354 112.302,165.227 112.575,165.227 112.702,165.354 112.975,165.354 113.102,165.227 113.375,165.227 113.502,165.354 113.775,165.354 113.902,165.227 114.175,165.227 114.302,165.354 114.575,165.354 114.702,165.227 114.975,165.227 115.102,165.354 115.375,165.354 115.502,165.227 115.775,165.227 115.902,165.354 116.175,165.354 116.302,165.227 116.575,165.227 116.702,165.354 116.975,165.354 117.102,165.227 117.375,165.227 117.502,165.354 117.775,165.354 117.902,165.227 118.175,165.227 118.302,165.354 118.575,165.354 118.702,165.227 118.975,165.227 119.102,165.354 119.375,165.354 119.502,165.227 119.775,165.227 119.902,165.354 120.175,165.354 120.302,165.227 120.575,165.227 120.702,165.354 120.975,165.354 121.102,165.227 121.375,165.227 121.502,165.354 121.775,165.354 121.902,165.227 122.175,165.227 122.302,165.354 122.575,165.354 122.702,165.227 122.975,165.227 123.102,165.354 123.375,165.354 123.502,165.227 123.775,165.227 123.902,165.354 124.175,165.354 124.302,165.227 124.575,165.227 124.702,165.354 124.975,165.354 125.102,165.227 125.375,165.227 125.502,165.354 125.775,165.354 125.902,165.227 126.175,165.227 126.302,165.354 126.575,165.354 126.702,165.227 126.975,165.227 127.102,165.354 127.375,165.354 127.502,165.227 127.775,165.227 127.902,165.354 128.175,165.354 128.302,165.227 128.575,165.227 128.702,165.354 128.975,165.354 129.102,165.227 129.375,165.227 129.502,165.354 129.775,165.354 129.902,165.227 130.175,165.227 130.302,165.354 130.575,165.354 130.702,165.227 130.975,165.227 131.102,165.354 131.375,165.354 131.502,165.227 131.775,165.227 131.902,165.354 132.175,165.354 132.302,165.227 132.575,165.227 132.702,165.354 132.975,165.354 133.102,165.227 133.375,165.227 133.502,165.354 133.775,165.354 133.902,165.227 134.175,165.227 134.302,165.354 134.575,165.354 134.947,164.982 134.947,164.803 135.13,164.62 135.23,164.62 135.242,164.632 135.342,164.632 135.525,164.449 135.525,164.349 135.371,164.195 135.371,164.095 135.553,163.912 135.653,163.912 135.808,164.066 135.908,164.066 136.091,163.883 136.091,163.783 135.985,163.678 135.985,163.578 136.168,163.395 136.268,163.395 136.373,163.501 136.473,163.501 136.707,163.267 136.807,163.267 136.926,163.386 137.026,163.386 137.208,163.203 137.208,163.103 137.09,162.984 137.09,162.884 137.272,162.702 137.372,162.702 137.491,162.82 137.591,162.82 137.774,162.638 137.774,162.538 137.655,162.419 137.655,162.319 137.838,162.136 137.938,162.136 138.057,162.255 138.157,162.255 138.34,162.072 138.34,161.972 138.221,161.853 138.221,161.753 138.391,161.583 138.391,161.243 138.462,161.172 138.486,161.172 138.557,161.101 138.557,160.843 138.486,160.772 138.462,160.772 138.391,160.701 138.391,160.443 138.462,160.372 138.486,160.372 138.557,160.301 138.557,160.043 138.486,159.972 138.462,159.972 138.391,159.901 138.391,157.915 U5.32@138.518,157.788
SD_A8: U1.A6 U5.33 | length 46.8
  Top Layer w0.1: U1.A6@106.077,159.289 111.634,164.846 111.934,164.846 112.005,164.917 112.005,164.927 112.075,164.998 112.334,164.998 112.405,164.927 112.405,164.917 112.475,164.846 112.734,164.846 112.805,164.917 112.805,164.927 112.875,164.998 113.134,164.998 113.205,164.927 113.205,164.917 113.275,164.846 113.534,164.846 113.605,164.917 113.605,164.927 113.675,164.998 113.934,164.998 114.005,164.927 114.005,164.917 114.075,164.846 114.334,164.846 114.405,164.917 114.405,164.927 114.475,164.998 114.734,164.998 114.805,164.927 114.805,164.917 114.875,164.846 115.134,164.846 115.205,164.917 115.205,164.927 115.275,164.998 115.534,164.998 115.605,164.927 115.605,164.917 115.675,164.846 115.934,164.846 116.005,164.917 116.005,164.927 116.075,164.998 116.334,164.998 116.405,164.927 116.405,164.917 116.475,164.846 116.734,164.846 116.805,164.917 116.805,164.927 116.875,164.998 117.134,164.998 117.205,164.927 117.205,164.917 117.275,164.846 117.534,164.846 117.605,164.917 117.605,164.927 117.675,164.998 117.934,164.998 118.005,164.927 118.005,164.917 118.075,164.846 118.334,164.846 118.405,164.917 118.405,164.927 118.475,164.998 118.734,164.998 118.805,164.927 118.805,164.917 118.875,164.846 119.134,164.846 119.205,164.917 119.205,164.927 119.275,164.998 119.534,164.998 119.605,164.927 119.605,164.917 119.675,164.846 119.934,164.846 120.005,164.917 120.005,164.927 120.075,164.998 120.334,164.998 120.405,164.927 120.405,164.917 120.475,164.846 120.734,164.846 120.805,164.917 120.805,164.927 120.875,164.998 121.134,164.998 121.205,164.927 121.205,164.917 121.275,164.846 121.534,164.846 121.605,164.917 121.605,164.927 121.675,164.998 121.934,164.998 122.005,164.927 122.005,164.917 122.075,164.846 122.334,164.846 122.405,164.917 122.405,164.927 122.475,164.998 122.734,164.998 122.805,164.927 122.805,164.917 122.875,164.846 123.134,164.846 123.205,164.917 123.205,164.927 123.275,164.998 123.534,164.998 123.605,164.927 123.605,164.917 123.675,164.846 123.934,164.846 124.005,164.917 124.005,164.927 124.075,164.998 124.334,164.998 124.405,164.927 124.405,164.917 124.475,164.846 124.734,164.846 124.805,164.917 124.805,164.927 124.875,164.998 125.134,164.998 125.205,164.927 125.205,164.917 125.275,164.846 125.534,164.846 125.605,164.917 125.605,164.927 125.675,164.998 125.934,164.998 126.005,164.927 126.005,164.917 126.075,164.846 126.334,164.846 126.405,164.917 126.405,164.927 126.475,164.998 126.734,164.998 126.805,164.927 126.805,164.917 126.875,164.846 127.134,164.846 127.205,164.917 127.205,164.927 127.275,164.998 127.534,164.998 127.605,164.927 127.605,164.917 127.675,164.846 127.934,164.846 128.005,164.917 128.005,164.927 128.075,164.998 128.334,164.998 128.405,164.927 128.405,164.917 128.475,164.846 128.734,164.846 128.805,164.917 128.805,164.927 128.875,164.998 129.134,164.998 129.205,164.927 129.205,164.917 129.275,164.846 129.534,164.846 129.605,164.917 129.605,164.927 129.675,164.998 129.934,164.998 130.005,164.927 130.005,164.917 130.075,164.846 130.334,164.846 130.405,164.917 130.405,164.927 130.475,164.998 130.734,164.998 130.805,164.927 130.805,164.917 130.875,164.846 131.134,164.846 131.205,164.917 131.205,164.927 131.275,164.998 131.534,164.998 131.605,164.927 131.605,164.917 131.675,164.846 131.934,164.846 132.005,164.917 132.005,164.927 132.075,164.998 132.334,164.998 132.405,164.927 132.405,164.917 132.475,164.846 132.734,164.846 132.805,164.917 132.805,164.927 132.875,164.998 133.134,164.998 133.205,164.927 133.205,164.917 133.275,164.846 133.534,164.846 133.605,164.917 133.605,164.927 133.675,164.998 133.934,164.998 134.005,164.927 134.005,164.917 134.075,164.846 134.366,164.846 134.578,164.634 134.578,164.534 134.566,164.522 134.566,164.422 134.749,164.239 134.849,164.239 134.861,164.251 134.961,164.251 135.144,164.068 135.144,163.968 135.088,163.913 135.088,163.813 135.271,163.63 135.371,163.63 135.427,163.685 135.527,163.685 135.71,163.502 135.71,163.402 135.654,163.347 135.654,163.247 135.837,163.064 135.937,163.064 135.992,163.12 136.092,163.12 136.275,162.937 136.275,162.837 136.22,162.781 136.22,162.681 136.403,162.499 136.503,162.499 136.558,162.554 136.658,162.554 136.841,162.371 136.841,162.271 136.794,162.225 136.794,162.125 136.977,161.942 137.077,161.942 137.124,161.988 137.224,161.988 137.922,161.29 137.922,161.069 137.851,160.998 137.358,160.998 137.287,160.927 137.287,160.669 137.358,160.598 137.851,160.598 137.922,160.527 137.922,160.269 137.851,160.198 137.358,160.198 137.287,160.127 137.287,159.869 137.358,159.798 137.851,159.798 137.922,159.727 137.922,159.444 137.851,159.373 137.739,159.373 137.668,159.302 137.668,159.044 137.739,158.973 137.851,158.973 137.922,158.902 137.922,157.992 U5.33@137.718,157.788
SD_A9: U1.A7 U5.34 | length 46.8
  Top Layer w0.1: U1.A7@106.877,159.289 110.308,162.72 110.308,162.82 110.17,162.958 110.17,163.058 110.353,163.24 110.453,163.24 110.591,163.103 110.691,163.103 110.874,163.285 110.874,163.385 110.736,163.523 110.736,163.623 110.918,163.806 111.018,163.806 111.156,163.668 111.256,163.668 111.439,163.851 111.439,163.951 111.301,164.089 111.301,164.189 111.484,164.372 111.584,164.372 111.722,164.234 111.822,164.234 112.053,164.465 112.353,164.465 112.424,164.536 112.424,164.546 112.495,164.617 112.753,164.617 112.824,164.546 112.824,164.536 112.895,164.465 113.153,164.465 113.224,164.536 113.224,164.546 113.295,164.617 113.553,164.617 113.624,164.546 113.624,164.536 113.695,164.465 113.953,164.465 114.024,164.536 114.024,164.546 114.095,164.617 114.353,164.617 114.424,164.546 114.424,164.536 114.495,164.465 114.753,164.465 114.824,164.536 114.824,164.546 114.895,164.617 115.153,164.617 115.224,164.546 115.224,164.536 115.295,164.465 115.553,164.465 115.624,164.536 115.624,164.546 115.695,164.617 115.953,164.617 116.024,164.546 116.024,164.536 116.095,164.465 116.353,164.465 116.424,164.536 116.424,164.546 116.495,164.617 116.753,164.617 116.824,164.546 116.824,164.536 116.895,164.465 117.153,164.465 117.224,164.536 117.224,164.546 117.295,164.617 117.553,164.617 117.624,164.546 117.624,164.536 117.695,164.465 117.953,164.465 118.024,164.536 118.024,164.546 118.095,164.617 118.353,164.617 118.424,164.546 118.424,164.536 118.495,164.465 118.753,164.465 118.824,164.536 118.824,164.546 118.895,164.617 119.153,164.617 119.224,164.546 119.224,164.536 119.295,164.465 119.553,164.465 119.624,164.536 119.624,164.546 119.695,164.617 119.953,164.617 120.024,164.546 120.024,164.536 120.095,164.465 120.353,164.465 120.424,164.536 120.424,164.546 120.495,164.617 120.753,164.617 120.824,164.546 120.824,164.536 120.895,164.465 121.153,164.465 121.224,164.536 121.224,164.546 121.295,164.617 121.553,164.617 121.624,164.546 121.624,164.536 121.695,164.465 121.953,164.465 122.024,164.536 122.024,164.546 122.095,164.617 122.353,164.617 122.424,164.546 122.424,164.536 122.495,164.465 122.753,164.465 122.824,164.536 122.824,164.546 122.895,164.617 123.153,164.617 123.224,164.546 123.224,164.536 123.295,164.465 123.553,164.465 123.624,164.536 123.624,164.546 123.695,164.617 123.953,164.617 124.024,164.546 124.024,164.536 124.095,164.465 124.353,164.465 124.424,164.536 124.424,164.546 124.495,164.617 124.753,164.617 124.824,164.546 124.824,164.536 124.895,164.465 125.153,164.465 125.224,164.536 125.224,164.546 125.295,164.617 125.553,164.617 125.624,164.546 125.624,164.536 125.695,164.465 125.953,164.465 126.024,164.536 126.024,164.546 126.095,164.617 126.353,164.617 126.424,164.546 126.424,164.536 126.495,164.465 126.753,164.465 126.824,164.536 126.824,164.546 126.895,164.617 127.153,164.617 127.224,164.546 127.224,164.536 127.295,164.465 127.553,164.465 127.624,164.536 127.624,164.546 127.695,164.617 127.953,164.617 128.024,164.546 128.024,164.536 128.095,164.465 128.353,164.465 128.424,164.536 128.424,164.546 128.495,164.617 128.753,164.617 128.824,164.546 128.824,164.536 128.895,164.465 129.153,164.465 129.224,164.536 129.224,164.546 129.295,164.617 129.553,164.617 129.624,164.546 129.624,164.536 129.695,164.465 129.953,164.465 130.024,164.536 130.024,164.546 130.095,164.617 130.353,164.617 130.424,164.546 130.424,164.536 130.495,164.465 130.753,164.465 130.824,164.536 130.824,164.546 130.895,164.617 131.153,164.617 131.224,164.546 131.224,164.536 131.295,164.465 131.553,164.465 131.624,164.536 131.624,164.546 131.695,164.617 131.953,164.617 132.024,164.546 132.024,164.536 132.095,164.465 132.353,164.465 132.424,164.536 132.424,164.546 132.495,164.617 132.753,164.617 132.824,164.546 132.824,164.536 132.895,164.465 133.153,164.465 133.224,164.536 133.224,164.546 133.295,164.617 133.553,164.617 133.624,164.546 133.624,164.536 133.695,164.465 134.112,164.465 134.324,164.253 134.324,164.153 134.312,164.141 134.312,164.041 134.495,163.858 134.595,163.858 134.607,163.87 134.707,163.87 134.89,163.687 134.89,163.587 134.834,163.532 134.834,163.432 135.017,163.249 135.117,163.249 135.173,163.304 135.273,163.304 135.456,163.121 135.456,163.021 135.4,162.966 135.4,162.866 135.583,162.683 135.683,162.683 135.738,162.739 135.838,162.739 136.021,162.556 136.021,162.456 135.966,162.4 135.966,162.3 136.149,162.118 136.249,162.118 136.304,162.173 136.404,162.173 136.847,161.73 136.847,161.651 136.777,161.58 136.469,161.58 136.398,161.51 136.398,161.251 136.469,161.18 136.847,161.18 136.918,161.11 136.918,160.851 136.847,160.78 136.469,160.78 136.398,160.71 136.398,160.451 136.469,160.38 136.847,160.38 136.918,160.31 136.918,160.051 136.847,159.98 136.469,159.98 136.398,159.91 136.398,159.651 136.469,159.58 136.847,159.58 136.918,159.51 136.918,159.251 136.847,159.18 136.469,159.18 136.398,159.11 136.398,158.851 136.469,158.78 136.847,158.78 136.918,158.71 U5.34@136.918,157.788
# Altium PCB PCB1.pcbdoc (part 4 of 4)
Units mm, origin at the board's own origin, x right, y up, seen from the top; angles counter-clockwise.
Board outline 96.27 x 122.17 mm, 4 copper layers (Top Layer, Inner1, Inner2, Bottom Layer); 135 components, 133 nets, 720 pads, 358 vias.

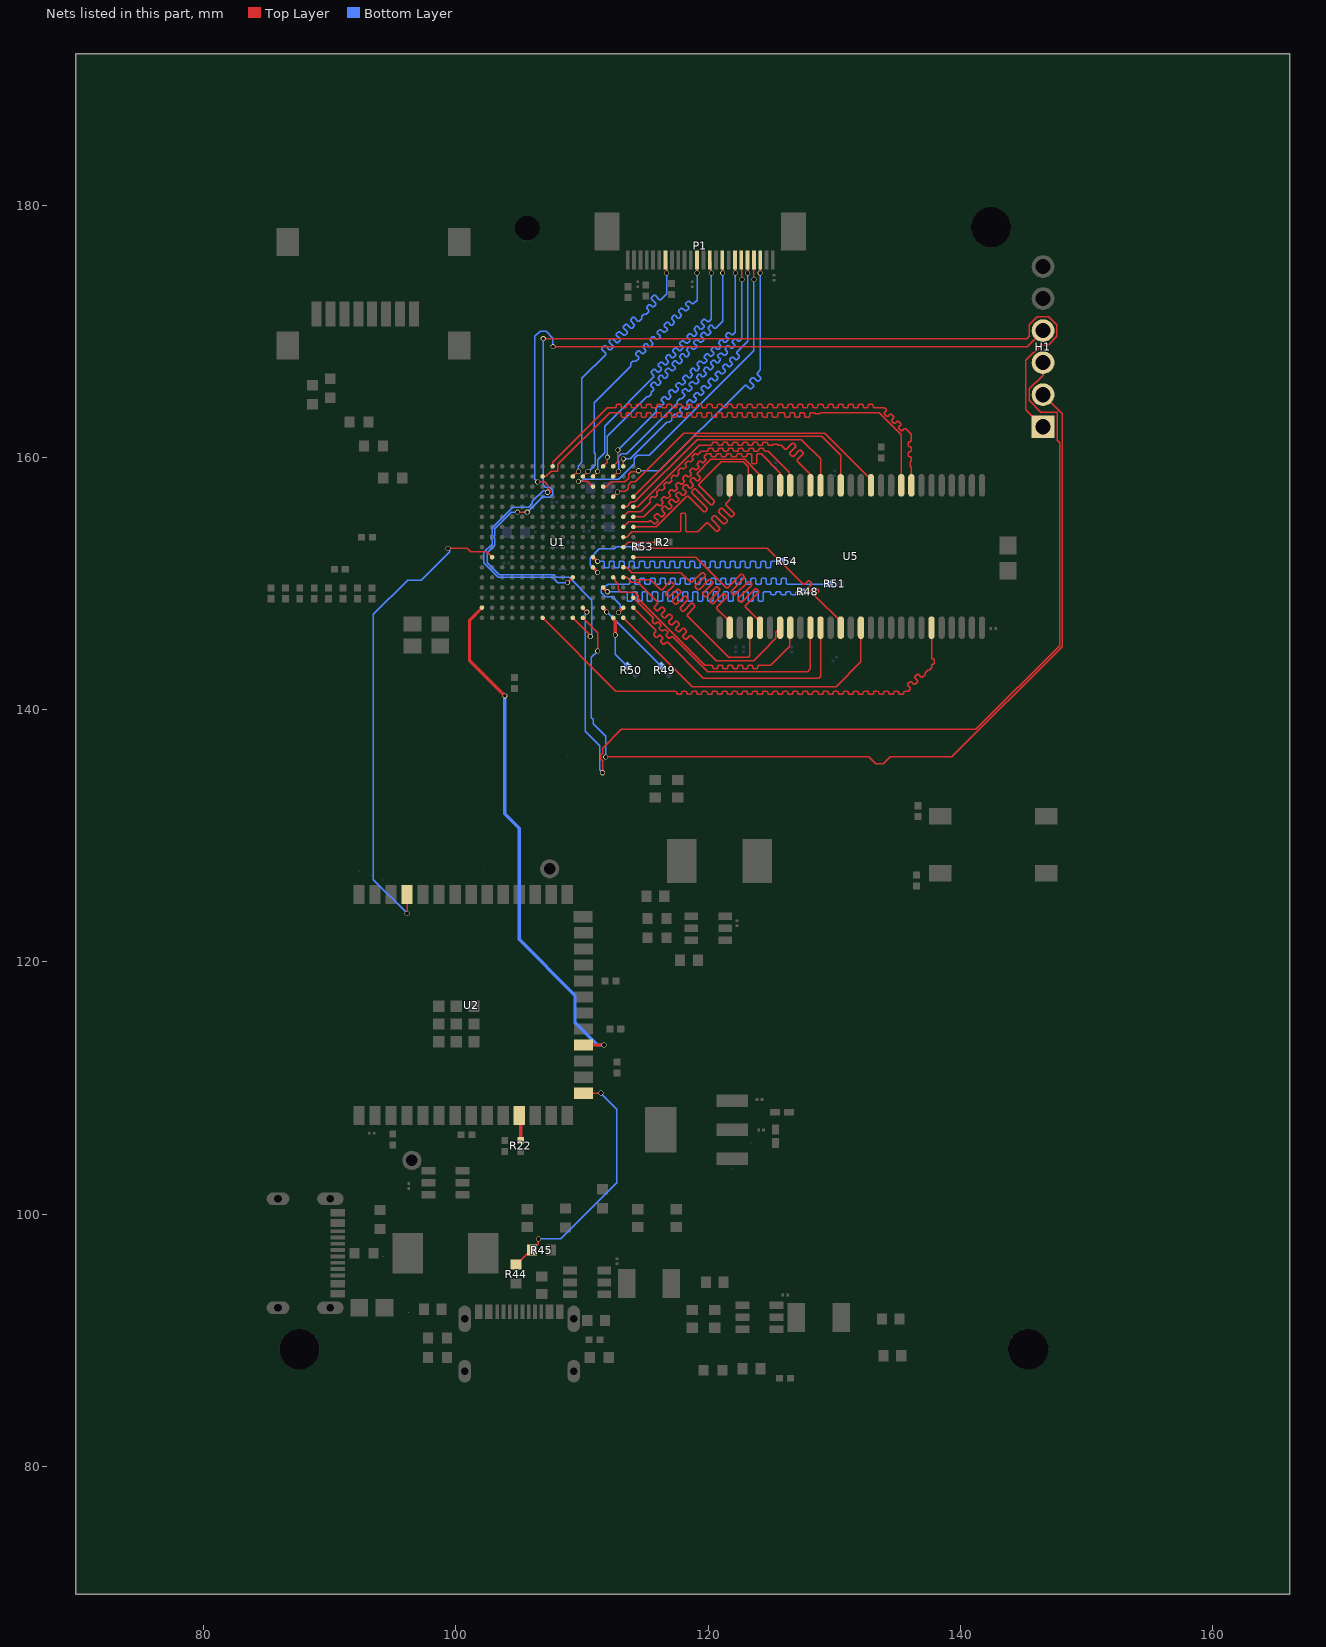
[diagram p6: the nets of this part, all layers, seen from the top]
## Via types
v1: diameter 0.4, hole 0.3, Top Layer to Bottom Layer, 324 vias
v2: diameter 1, hole 0.5, Top Layer to Bottom Layer, 33 vias
v3: diameter 0.5, hole 0.3, Top Layer to Bottom Layer, 1 vias

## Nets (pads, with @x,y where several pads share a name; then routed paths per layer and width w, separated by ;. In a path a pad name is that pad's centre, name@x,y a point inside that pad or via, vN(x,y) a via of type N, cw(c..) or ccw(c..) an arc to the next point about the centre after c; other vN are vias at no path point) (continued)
SD_A10: U1.T7 U5.22 | length 46.9
  Top Layer w0.1: U1.T7@106.877,147.289 112.688,141.478 117.449,141.478 117.519,141.407 117.519,141.295 117.59,141.224 117.849,141.224 117.919,141.295 117.919,141.407 117.99,141.478 118.249,141.478 118.319,141.407 118.319,141.295 118.39,141.224 118.649,141.224 118.719,141.295 118.719,141.407 118.79,141.478 119.049,141.478 119.119,141.407 119.119,141.295 119.19,141.224 119.449,141.224 119.519,141.295 119.519,141.407 119.59,141.478 119.849,141.478 119.919,141.407 119.919,141.295 119.99,141.224 120.249,141.224 120.319,141.295 120.319,141.407 120.39,141.478 120.649,141.478 120.719,141.407 120.719,141.295 120.79,141.224 121.049,141.224 121.119,141.295 121.119,141.407 121.19,141.478 121.449,141.478 121.519,141.407 121.519,141.295 121.59,141.224 121.849,141.224 121.919,141.295 121.919,141.407 121.99,141.478 122.249,141.478 122.319,141.407 122.319,141.295 122.39,141.224 122.649,141.224 122.719,141.295 122.719,141.407 122.79,141.478 123.049,141.478 123.119,141.407 123.119,141.295 123.19,141.224 123.449,141.224 123.519,141.295 123.519,141.407 123.59,141.478 123.849,141.478 123.919,141.407 123.919,141.295 123.99,141.224 124.249,141.224 124.319,141.295 124.319,141.407 124.39,141.478 124.649,141.478 124.719,141.407 124.719,141.295 124.79,141.224 125.049,141.224 125.119,141.295 125.119,141.407 125.19,141.478 125.449,141.478 125.519,141.407 125.519,141.295 125.59,141.224 125.849,141.224 125.919,141.295 125.919,141.407 125.99,141.478 126.249,141.478 126.319,141.407 126.319,141.295 126.39,141.224 126.649,141.224 126.719,141.295 126.719,141.407 126.79,141.478 127.049,141.478 127.119,141.407 127.119,141.295 127.19,141.224 127.449,141.224 127.519,141.295 127.519,141.407 127.59,141.478 127.849,141.478 127.919,141.407 127.919,141.295 127.99,141.224 128.249,141.224 128.319,141.295 128.319,141.407 128.39,141.478 128.649,141.478 128.719,141.407 128.719,141.295 128.79,141.224 129.049,141.224 129.119,141.295 129.119,141.407 129.19,141.478 129.449,141.478 129.519,141.407 129.519,141.295 129.59,141.224 129.849,141.224 129.919,141.295 129.919,141.407 129.99,141.478 130.249,141.478 130.319,141.407 130.319,141.295 130.39,141.224 130.649,141.224 130.719,141.295 130.719,141.407 130.79,141.478 131.049,141.478 131.119,141.407 131.119,141.295 131.19,141.224 131.449,141.224 131.519,141.295 131.519,141.407 131.59,141.478 131.849,141.478 131.919,141.407 131.919,141.295 131.99,141.224 132.249,141.224 132.319,141.295 132.319,141.407 132.39,141.478 132.649,141.478 132.719,141.407 132.719,141.295 132.79,141.224 133.049,141.224 133.119,141.295 133.119,141.407 133.19,141.478 133.449,141.478 133.519,141.407 133.519,141.295 133.59,141.224 133.849,141.224 133.919,141.295 133.919,141.407 133.99,141.478 134.249,141.478 134.319,141.407 134.319,141.295 134.39,141.224 134.649,141.224 134.719,141.295 134.719,141.407 134.79,141.478 135.049,141.478 135.119,141.407 135.119,141.295 135.19,141.224 135.449,141.224 135.519,141.295 135.519,141.407 135.59,141.478 135.89,141.478 136.044,141.632 136.044,141.732 135.826,141.949 135.826,142.049 136.009,142.232 136.109,142.232 136.327,142.015 136.427,142.015 136.61,142.198 136.61,142.298 136.392,142.515 136.392,142.615 136.575,142.798 136.675,142.798 136.893,142.581 136.993,142.581 137.202,142.79 137.202,142.931 137.414,143.143 137.555,143.143 137.718,143.306 137.718,143.549 137.789,143.62 137.851,143.62 137.922,143.69 137.922,143.949 137.851,144.02 137.789,144.02 137.718,144.09 U5.22@137.718,146.504
SD_A11: U1.A8 U5.35 | length 46.7
  Top Layer w0.1: U1.A8@107.677,159.289 107.677,159.62 112.014,163.957 112.645,163.957 112.716,164.028 112.716,164.14 112.786,164.211 113.045,164.211 113.116,164.14 113.116,164.028 113.186,163.957 113.445,163.957 113.516,164.028 113.516,164.14 113.586,164.211 113.845,164.211 113.916,164.14 113.916,164.028 113.986,163.957 114.245,163.957 114.316,164.028 114.316,164.14 114.386,164.211 114.645,164.211 114.716,164.14 114.716,164.028 114.786,163.957 115.045,163.957 115.116,164.028 115.116,164.14 115.186,164.211 115.445,164.211 115.516,164.14 115.516,164.028 115.586,163.957 115.845,163.957 115.916,164.028 115.916,164.14 115.986,164.211 116.245,164.211 116.316,164.14 116.316,164.028 116.386,163.957 116.645,163.957 116.716,164.028 116.716,164.14 116.786,164.211 117.045,164.211 117.116,164.14 117.116,164.028 117.186,163.957 117.445,163.957 117.516,164.028 117.516,164.14 117.586,164.211 117.845,164.211 117.916,164.14 117.916,164.028 117.986,163.957 118.245,163.957 118.316,164.028 118.316,164.14 118.386,164.211 118.645,164.211 118.716,164.14 118.716,164.028 118.786,163.957 119.045,163.957 119.116,164.028 119.116,164.14 119.186,164.211 119.445,164.211 119.516,164.14 119.516,164.028 119.586,163.957 119.845,163.957 119.916,164.028 119.916,164.14 119.986,164.211 120.245,164.211 120.316,164.14 120.316,164.028 120.386,163.957 120.645,163.957 120.716,164.028 120.716,164.14 120.786,164.211 121.045,164.211 121.116,164.14 121.116,164.028 121.186,163.957 121.445,163.957 121.516,164.028 121.516,164.14 121.586,164.211 121.845,164.211 121.916,164.14 121.916,164.028 121.986,163.957 122.245,163.957 122.316,164.028 122.316,164.14 122.386,164.211 122.645,164.211 122.716,164.14 122.716,164.028 122.786,163.957 123.045,163.957 123.116,164.028 123.116,164.14 123.186,164.211 123.445,164.211 123.516,164.14 123.516,164.028 123.586,163.957 123.845,163.957 123.916,164.028 123.916,164.14 123.986,164.211 124.245,164.211 124.316,164.14 124.316,164.028 124.386,163.957 124.645,163.957 124.716,164.028 124.716,164.14 124.786,164.211 125.045,164.211 125.116,164.14 125.116,164.028 125.186,163.957 125.445,163.957 125.516,164.028 125.516,164.14 125.586,164.211 125.845,164.211 125.916,164.14 125.916,164.028 125.986,163.957 126.245,163.957 126.316,164.028 126.316,164.14 126.386,164.211 126.645,164.211 126.716,164.14 126.716,164.028 126.786,163.957 127.045,163.957 127.116,164.028 127.116,164.14 127.186,164.211 127.445,164.211 127.516,164.14 127.516,164.028 127.586,163.957 127.845,163.957 127.916,164.028 127.916,164.14 127.986,164.211 128.245,164.211 128.316,164.14 128.316,164.028 128.386,163.957 128.645,163.957 128.716,164.028 128.716,164.14 128.786,164.211 129.045,164.211 129.116,164.14 129.116,164.028 129.186,163.957 129.445,163.957 129.516,164.028 129.516,164.14 129.586,164.211 129.845,164.211 129.916,164.14 129.916,164.028 129.986,163.957 130.245,163.957 130.316,164.028 130.316,164.14 130.386,164.211 130.645,164.211 130.716,164.14 130.716,164.028 130.786,163.957 131.045,163.957 131.116,164.028 131.116,164.14 131.186,164.211 131.445,164.211 131.516,164.14 131.516,164.028 131.586,163.957 131.845,163.957 131.916,164.028 131.916,164.14 131.986,164.211 132.245,164.211 132.316,164.14 132.316,164.028 132.386,163.957 132.645,163.957 132.716,164.028 132.716,164.14 132.786,164.211 133.045,164.211 133.116,164.14 133.116,164.028 133.186,163.957 133.985,163.957 134.14,163.802 134.14,163.702 133.986,163.548 133.986,163.448 134.169,163.265 134.269,163.265 134.423,163.419 134.523,163.419 134.706,163.236 134.706,163.136 134.552,162.982 134.552,162.882 134.735,162.699 134.835,162.699 134.989,162.853 135.089,162.853 135.272,162.67 135.272,162.57 135.118,162.416 135.118,162.316 135.301,162.133 135.401,162.133 135.555,162.287 135.655,162.287 136.118,161.824 136.118,161.306 136.047,161.235 135.961,161.235 135.89,161.164 135.89,160.906 135.961,160.835 136.047,160.835 136.118,160.764 136.118,160.506 136.047,160.435 135.961,160.435 135.89,160.364 135.89,160.106 135.961,160.035 136.047,160.035 136.118,159.964 136.118,159.742 136.017,159.641 136.017,159.342 136.118,159.241 U5.35@136.118,157.788
SD_A12: U1.B7 U5.36 | length 46.8
  Top Layer w0.1: U1.B7@106.877,158.489 107.137,158.489 107.555,158.907 108.07,158.907 108.095,158.932 108.095,159.447 112.197,163.549 113.037,163.549 113.108,163.478 113.108,163.239 113.178,163.168 113.437,163.168 113.508,163.239 113.508,163.478 113.578,163.549 113.837,163.549 113.908,163.478 113.908,163.239 113.978,163.168 114.237,163.168 114.308,163.239 114.308,163.478 114.378,163.549 114.637,163.549 114.708,163.478 114.708,163.239 114.778,163.168 115.037,163.168 115.108,163.239 115.108,163.478 115.178,163.549 115.437,163.549 115.508,163.478 115.508,163.239 115.578,163.168 115.837,163.168 115.908,163.239 115.908,163.478 115.978,163.549 116.237,163.549 116.308,163.478 116.308,163.239 116.378,163.168 116.637,163.168 116.708,163.239 116.708,163.478 116.778,163.549 117.037,163.549 117.108,163.478 117.108,163.239 117.178,163.168 117.437,163.168 117.508,163.239 117.508,163.478 117.578,163.549 117.837,163.549 117.908,163.478 117.908,163.239 117.978,163.168 118.237,163.168 118.308,163.239 118.308,163.478 118.378,163.549 118.637,163.549 118.708,163.478 118.708,163.239 118.778,163.168 119.037,163.168 119.108,163.239 119.108,163.478 119.178,163.549 119.437,163.549 119.508,163.478 119.508,163.239 119.578,163.168 119.837,163.168 119.908,163.239 119.908,163.478 119.978,163.549 120.237,163.549 120.308,163.478 120.308,163.239 120.378,163.168 120.637,163.168 120.708,163.239 120.708,163.478 120.778,163.549 121.037,163.549 121.108,163.478 121.108,163.239 121.178,163.168 121.437,163.168 121.508,163.239 121.508,163.478 121.578,163.549 121.837,163.549 121.908,163.478 121.908,163.239 121.978,163.168 122.237,163.168 122.308,163.239 122.308,163.478 122.378,163.549 122.637,163.549 122.708,163.478 122.708,163.239 122.778,163.168 123.037,163.168 123.108,163.239 123.108,163.478 123.178,163.549 123.437,163.549 123.508,163.478 123.508,163.239 123.578,163.168 123.837,163.168 123.908,163.239 123.908,163.478 123.978,163.549 124.237,163.549 124.308,163.478 124.308,163.239 124.378,163.168 124.637,163.168 124.708,163.239 124.708,163.478 124.778,163.549 125.037,163.549 125.108,163.478 125.108,163.239 125.178,163.168 125.437,163.168 125.508,163.239 125.508,163.478 125.578,163.549 125.993,163.549 126.063,163.478 126.063,163.266 126.134,163.195 126.393,163.195 126.463,163.266 126.463,163.478 126.534,163.549 126.793,163.549 126.863,163.478 126.863,163.266 126.934,163.195 127.193,163.195 127.263,163.266 127.263,163.478 127.334,163.549 127.593,163.549 127.663,163.478 127.663,163.266 127.734,163.195 127.993,163.195 128.063,163.266 128.063,163.478 128.134,163.549 128.416,163.549 128.516,163.449 128.816,163.449 128.916,163.549 133.577,163.549 135.318,161.808 U5.36@135.318,157.788
SD_BA0: R54.1 U1.K12 | length 29.1
  Top Layer w0.254: U1.K12@110.877,152.089 111.203,151.763 v1(111.25,151.763)
  Bottom Layer w0.1: v1(111.25,151.763) 111.691,151.763 111.762,151.693 111.762,151.337 111.833,151.266 112.091,151.266 112.162,151.337 112.162,151.693 112.233,151.763 112.491,151.763 112.562,151.693 112.562,151.337 112.633,151.266 112.891,151.266 112.962,151.337 112.962,151.693 113.033,151.763 113.291,151.763 113.362,151.693 113.362,151.337 113.433,151.266 113.691,151.266 113.762,151.337 113.762,151.693 113.833,151.763 114.091,151.763 114.162,151.693 114.162,151.337 114.233,151.266 114.491,151.266 114.562,151.337 114.562,151.693 114.633,151.763 114.891,151.763 114.962,151.693 114.962,151.337 115.033,151.266 115.291,151.266 115.362,151.337 115.362,151.693 115.433,151.763 115.691,151.763 115.762,151.693 115.762,151.337 115.833,151.266 116.091,151.266 116.162,151.337 116.162,151.693 116.233,151.763 116.491,151.763 116.562,151.693 116.562,151.337 116.633,151.266 116.891,151.266 116.962,151.337 116.962,151.693 117.033,151.763 117.291,151.763 117.362,151.693 117.362,151.337 117.433,151.266 117.691,151.266 117.762,151.337 117.762,151.693 117.833,151.763 118.091,151.763 118.162,151.693 118.162,151.337 118.233,151.266 118.491,151.266 118.562,151.337 118.562,151.693 118.633,151.763 118.891,151.763 118.962,151.693 118.962,151.337 119.033,151.266 119.291,151.266 119.362,151.337 119.362,151.693 119.433,151.763 119.691,151.763 119.762,151.693 119.762,151.337 119.833,151.266 120.091,151.266 120.162,151.337 120.162,151.693 120.233,151.763 120.491,151.763 120.562,151.693 120.562,151.337 120.633,151.266 120.891,151.266 120.962,151.337 120.962,151.693 121.033,151.763 121.291,151.763 121.362,151.693 121.362,151.337 121.433,151.266 121.691,151.266 121.762,151.337 121.762,151.693 121.833,151.763 122.091,151.763 122.162,151.693 122.162,151.337 122.233,151.266 122.491,151.266 122.562,151.337 122.562,151.693 122.633,151.763 122.891,151.763 122.962,151.693 122.962,151.337 123.033,151.266 123.291,151.266 123.362,151.337 123.362,151.693 123.433,151.763 123.691,151.763 123.762,151.693 123.762,151.337 123.833,151.266 124.091,151.266 124.162,151.337 124.162,151.693 124.233,151.763 124.491,151.763 124.562,151.693 124.562,151.337 124.633,151.266 124.891,151.266 124.962,151.337 124.962,151.693 125.033,151.763 R54.1@125.805,151.763
SD_BA1: R53.1 U1.L12 | length 6.1
  Top Layer w0.254: U1.L12@110.877,151.289 111.252,150.914 v1(111.252,150.876)
  Bottom Layer w0.1: v1(111.252,150.876) 110.648,151.48 110.648,152.013 111.389,152.753 112.581,152.753 112.736,152.908 R53.1@114.375,152.908
SD_CAS_N: R49.1 U1.R13 | length 6.6
  Top Layer w0.254: U1.R13@111.677,148.089 111.677,148.041 v1(111.966,147.753)
  Bottom Layer w0.1: v1(111.966,147.753) R49.1@116.282,143.437
SD_CLK: R2.2 U1.J15 | length 2.9
  Top Layer w0.1: U1.J15@113.277,152.889 113.677,153.289 R2.2@116.026,153.289
SD_CS_N: R51.1 U1.R15 | length 34.2
  Top Layer w0.254: v1(112.903,147.701) 113.277,148.075 U1.R15@113.277,148.089
  Bottom Layer w0.1: v1(112.903,147.701) 113.03,147.701 113.03,148.336 112.416,148.95 111.847,148.95 111.535,149.262 111.535,149.55 111.816,149.831 111.943,149.831 112.07,149.958 113.73,149.958 113.8,150.029 113.8,150.358 113.871,150.429 114.13,150.429 114.2,150.358 114.2,150.029 114.271,149.958 114.53,149.958 114.6,150.029 114.6,150.358 114.671,150.429 114.93,150.429 115,150.358 115,150.029 115.071,149.958 115.33,149.958 115.4,150.029 115.4,150.358 115.471,150.429 115.73,150.429 115.8,150.358 115.8,150.029 115.871,149.958 116.13,149.958 116.2,150.029 116.2,150.358 116.271,150.429 116.53,150.429 116.6,150.358 116.6,150.029 116.671,149.958 116.93,149.958 117,150.029 117,150.358 117.071,150.429 117.33,150.429 117.4,150.358 117.4,150.029 117.471,149.958 117.73,149.958 117.8,150.029 117.8,150.358 117.871,150.429 118.13,150.429 118.2,150.358 118.2,150.029 118.271,149.958 118.53,149.958 118.6,150.029 118.6,150.358 118.671,150.429 118.93,150.429 119,150.358 119,150.029 119.071,149.958 119.33,149.958 119.4,150.029 119.4,150.358 119.471,150.429 119.73,150.429 119.8,150.358 119.8,150.029 119.871,149.958 120.13,149.958 120.2,150.029 120.2,150.358 120.271,150.429 120.53,150.429 120.6,150.358 120.6,150.029 120.671,149.958 120.93,149.958 121,150.029 121,150.358 121.071,150.429 121.33,150.429 121.4,150.358 121.4,150.029 121.471,149.958 121.73,149.958 121.8,150.029 121.8,150.358 121.871,150.429 122.13,150.429 122.2,150.358 122.2,150.029 122.271,149.958 122.53,149.958 122.6,150.029 122.6,150.358 122.671,150.429 122.93,150.429 123,150.358 123,150.029 123.071,149.958 123.33,149.958 123.4,150.029 123.4,150.358 123.471,150.429 123.73,150.429 123.8,150.358 123.8,150.029 123.871,149.958 124.13,149.958 124.2,150.029 124.2,150.358 124.271,150.429 124.53,150.429 124.6,150.358 124.6,150.029 124.671,149.958 124.93,149.958 125,150.029 125,150.358 125.071,150.429 125.33,150.429 125.4,150.358 125.4,150.029 125.471,149.958 125.73,149.958 125.8,150.029 125.8,150.358 125.871,150.429 126.13,150.429 126.2,150.358 126.2,150.029 126.271,149.958 129.586,149.958 R51.1@129.615,149.987
SD_DQ0: U1.L15 U5.2 | length 20.1
  Top Layer w0.1: U1.L15@113.277,151.289 113.537,151.289 113.955,150.871 117.84,150.871 118.62,150.091 118.72,150.091 119.505,150.877 119.605,150.877 119.788,150.694 119.788,150.594 119.003,149.808 119.003,149.708 119.186,149.526 119.286,149.526 120.071,150.311 120.171,150.311 120.354,150.128 120.354,150.028 119.568,149.243 119.568,149.143 119.751,148.96 119.851,148.96 120.637,149.745 120.737,149.745 120.92,149.562 120.92,149.463 120.134,148.677 120.134,148.577 120.317,148.394 120.417,148.394 121.202,149.18 121.302,149.18 121.485,148.997 121.485,148.897 120.7,148.111 120.7,148.011 121.718,146.993 U5.2@121.718,146.504
SD_DQ1: U1.M16 U5.4 | length 21.6
  Top Layer w0.1: U1.M16@114.077,150.489 114.259,150.307 115.465,150.307 116.263,149.509 116.363,149.509 116.981,150.127 117.081,150.127 117.264,149.944 117.264,149.844 116.646,149.226 116.646,149.126 116.828,148.943 116.928,148.943 117.547,149.561 117.647,149.561 117.83,149.378 117.83,149.278 117.211,148.66 117.211,148.56 117.394,148.377 117.494,148.377 118.112,148.996 118.212,148.996 118.395,148.813 118.395,148.713 117.777,148.094 117.777,147.994 117.96,147.812 118.06,147.812 118.678,148.43 118.778,148.43 118.961,148.247 118.961,148.147 118.343,147.529 118.343,147.429 121.626,144.145 123.19,144.145 123.318,144.273 U5.4@123.318,146.504
SD_DQ2: U1.K16 U5.5 | length 22
  Top Layer w0.1: U1.K16@114.077,152.089 119.022,152.089 121.445,149.666 121.545,149.666 122.604,150.724 122.704,150.724 122.887,150.541 122.887,150.441 121.828,149.383 121.828,149.283 122.011,149.1 122.111,149.1 123.17,150.159 123.27,150.159 123.452,149.976 123.452,149.876 122.394,148.817 122.394,148.717 122.577,148.534 122.677,148.534 123.735,149.593 123.835,149.593 124.018,149.41 124.018,149.31 122.96,148.252 122.96,148.152 124.118,146.993 U5.5@124.118,146.504
SD_DQ3: U1.M15 U5.7 | length 21.1
  Top Layer w0.1: U1.M15@113.277,150.489 113.537,150.489 113.919,150.107 114.434,150.107 116.02,148.521 116.02,148.421 115.739,148.14 115.739,148.04 115.922,147.857 116.022,147.857 116.303,148.138 116.403,148.138 116.585,147.956 116.585,147.856 116.304,147.575 116.304,147.475 116.487,147.292 116.587,147.292 116.868,147.573 116.968,147.573 117.151,147.39 117.151,147.29 116.87,147.009 116.87,146.909 117.053,146.726 117.153,146.726 117.434,147.007 117.534,147.007 117.717,146.824 117.717,146.724 117.436,146.443 117.436,146.343 117.619,146.16 117.719,146.16 118,146.441 118.1,146.441 118.282,146.259 118.282,146.159 118.001,145.878 118.001,145.778 118.184,145.595 118.284,145.595 118.565,145.876 118.665,145.876 120.65,143.891 123.632,143.891 124.862,145.121 124.862,145.159 125.37,145.667 125.37,146.156 U5.7@125.718,146.504
SD_DQ4: U1.M14 U5.8 | length 21.2
  Top Layer w0.1: U1.M14@112.477,150.489 112.659,150.307 112.659,150.175 112.895,149.939 112.895,149.531 113.119,149.307 114.199,149.307 114.459,149.047 114.459,148.79 119.739,143.51 120.288,143.51 120.358,143.439 120.358,143.327 120.429,143.256 120.688,143.256 120.758,143.327 120.758,143.439 120.829,143.51 121.088,143.51 121.158,143.439 121.158,143.327 121.229,143.256 121.488,143.256 121.558,143.327 121.558,143.439 121.629,143.51 121.888,143.51 121.958,143.439 121.958,143.327 122.029,143.256 122.288,143.256 122.358,143.327 122.358,143.439 122.429,143.51 122.688,143.51 122.758,143.439 122.758,143.327 122.829,143.256 123.088,143.256 123.158,143.327 123.158,143.439 123.229,143.51 123.488,143.51 123.558,143.439 123.558,143.327 123.629,143.256 123.888,143.256 123.958,143.327 123.958,143.439 124.029,143.51 124.968,143.51 126.492,145.034 126.492,146.478 U5.8@126.518,146.504
SD_DQ5: U1.P16 U5.10 | length 21
  Top Layer w0.1: U1.P16@114.077,148.889 115.669,147.297 115.669,147.197 115.569,147.097 115.569,146.997 115.752,146.814 115.852,146.814 115.952,146.914 116.052,146.914 116.235,146.731 116.235,146.631 116.135,146.531 116.135,146.431 116.318,146.249 116.418,146.249 116.518,146.348 116.618,146.348 116.8,146.166 116.8,146.066 116.701,145.966 116.701,145.866 116.884,145.683 116.984,145.683 117.083,145.783 117.183,145.783 119.964,143.002 127.889,143.002 128.118,143.231 U5.10@128.118,146.504
SD_DQ6: U1.R16 U5.11 | length 22
  Top Layer w0.1: U1.R16@114.173,147.955 115.841,146.287 115.841,146.187 115.687,146.033 115.687,145.933 115.87,145.75 115.97,145.75 116.124,145.904 116.224,145.904 116.406,145.722 116.406,145.622 116.252,145.468 116.252,145.368 116.435,145.185 116.535,145.185 116.689,145.339 116.789,145.339 119.634,142.494 128.778,142.494 128.918,142.634 U5.11@128.918,146.504
SD_DQ7: U1.J16 U5.13 | length 21.2
  Top Layer w0.1: U1.J16@114.077,152.889 115.588,152.889 115.66,152.817 124.694,152.817 127.557,149.954 127.657,149.954 127.93,150.227 128.03,150.227 128.213,150.044 128.213,149.944 127.94,149.671 127.94,149.571 128.123,149.388 128.223,149.388 128.496,149.661 128.596,149.661 128.779,149.478 128.779,149.378 128.506,149.105 128.506,149.005 130.518,146.993 U5.13@130.518,146.504
SD_DQ8: U1.D16 U5.42 | length 21.4
  Top Layer w0.1: U1.D16@114.077,156.889 118.859,161.671 129.032,161.671 130.518,160.185 U5.42@130.518,157.788
SD_DQ9: U1.E15 U5.44 | length 20.6
  Top Layer w0.1: U1.E15@113.277,156.089 113.537,156.089 113.919,156.471 114.199,156.471 119.145,161.417 127.381,161.417 128.918,159.88 U5.44@128.918,157.788
SD_DQ10: U1.E16 U5.45 | length 22.6
  Top Layer w0.1: U1.E16@114.077,156.089 114.433,156.089 119.307,160.963 120.282,160.963 120.352,161.034 120.352,161.117 120.423,161.188 120.682,161.188 120.752,161.117 120.752,161.034 120.823,160.963 121.082,160.963 121.152,161.034 121.152,161.117 121.223,161.188 121.482,161.188 121.552,161.117 121.552,161.034 121.623,160.963 121.882,160.963 121.952,161.034 121.952,161.117 122.023,161.188 122.282,161.188 122.352,161.117 122.352,161.034 122.423,160.963 122.682,160.963 122.752,161.034 122.752,161.117 122.823,161.188 123.082,161.188 123.152,161.117 123.152,161.034 123.223,160.963 123.482,160.963 123.552,161.034 123.552,161.117 123.623,161.188 123.882,161.188 123.952,161.117 123.952,161.034 124.023,160.963 124.282,160.963 124.352,161.034 124.352,161.117 124.423,161.188 124.682,161.188 124.752,161.117 124.752,161.034 124.823,160.963 125.082,160.963 125.182,161.063 125.482,161.063 125.582,160.963 125.803,160.963 126.111,160.655 126.211,160.655 126.682,161.127 126.782,161.127 126.965,160.944 126.965,160.844 126.494,160.372 126.494,160.272 126.677,160.089 126.777,160.089 127.248,160.561 127.348,160.561 127.531,160.378 127.531,160.278 127.06,159.806 127.06,159.706 128.118,158.648 U5.45@128.118,157.788
SD_DQ11: U1.F15 U5.47 | length 21.1
  Top Layer w0.1: U1.F15@113.277,155.289 113.69,155.702 114.681,155.702 115.424,156.445 115.424,156.545 115.368,156.6 115.368,156.7 115.551,156.883 115.651,156.883 115.707,156.828 115.807,156.828 115.99,157.011 115.99,157.111 115.934,157.166 115.934,157.266 116.117,157.449 116.217,157.449 116.272,157.393 116.372,157.393 116.555,157.576 116.555,157.676 116.5,157.732 116.5,157.832 116.683,158.014 116.783,158.014 116.838,157.959 116.938,157.959 117.121,158.142 117.121,158.242 117.066,158.297 117.066,158.397 117.248,158.58 117.348,158.58 117.404,158.525 117.504,158.525 117.687,158.708 117.687,158.808 117.631,158.863 117.631,158.963 117.814,159.146 117.914,159.146 117.969,159.09 118.069,159.09 118.252,159.273 118.252,159.373 118.197,159.429 118.197,159.529 118.38,159.712 118.48,159.712 118.535,159.656 118.635,159.656 118.818,159.839 118.818,159.939 118.763,159.994 118.763,160.094 118.945,160.277 119.045,160.277 119.101,160.222 119.201,160.222 119.453,160.474 119.936,160.474 120.007,160.545 120.007,160.663 120.078,160.734 120.336,160.734 120.407,160.663 120.407,160.545 120.478,160.474 120.736,160.474 120.807,160.545 120.807,160.663 120.878,160.734 121.136,160.734 121.207,160.663 121.207,160.545 121.278,160.474 121.536,160.474 121.607,160.545 121.607,160.663 121.678,160.734 121.936,160.734 122.007,160.663 122.007,160.545 122.078,160.474 122.336,160.474 122.407,160.545 122.407,160.663 122.478,160.734 122.736,160.734 122.807,160.663 122.807,160.545 122.878,160.474 123.136,160.474 123.207,160.545 123.207,160.663 123.278,160.734 123.536,160.734 123.607,160.663 123.607,160.545 123.678,160.474 123.936,160.474 124.007,160.545 124.007,160.663 124.078,160.734 124.336,160.734 124.407,160.663 124.407,160.545 124.478,160.474 124.768,160.474 126.418,158.824 126.418,157.888 U5.47@126.518,157.788
SD_DQ12: U1.F16 U5.48 | length 20.9
  Top Layer w0.1: U1.F16@114.077,155.289 114.903,155.289 115.92,156.306 116.02,156.306 116.139,156.187 116.239,156.187 116.422,156.37 116.422,156.47 116.303,156.589 116.303,156.689 116.486,156.872 116.586,156.872 116.704,156.753 116.804,156.753 116.987,156.936 116.987,157.036 116.868,157.154 116.868,157.254 117.051,157.437 117.151,157.437 117.27,157.318 117.37,157.318 117.553,157.501 117.553,157.601 117.434,157.72 117.434,157.82 117.617,158.003 117.717,158.003 117.836,157.884 117.936,157.884 118.119,158.067 118.119,158.167 118,158.286 118,158.386 118.183,158.569 118.283,158.569 118.402,158.45 118.502,158.45 118.684,158.633 118.684,158.733 118.565,158.851 118.565,158.951 118.748,159.134 118.848,159.134 118.967,159.015 119.067,159.015 119.25,159.198 119.25,159.298 119.131,159.417 119.131,159.517 119.314,159.7 119.414,159.7 119.533,159.581 119.633,159.581 119.816,159.764 119.816,159.864 119.697,159.983 119.697,160.083 119.888,160.274 120.188,160.274 120.259,160.203 120.259,160.139 120.329,160.068 120.588,160.068 120.659,160.139 120.659,160.203 120.729,160.274 120.988,160.274 121.059,160.203 121.059,160.139 121.129,160.068 121.388,160.068 121.459,160.139 121.459,160.203 121.529,160.274 121.788,160.274 121.859,160.203 121.859,160.139 121.929,160.068 122.188,160.068 122.259,160.139 122.259,160.203 122.329,160.274 122.588,160.274 122.659,160.203 122.659,160.139 122.729,160.068 122.988,160.068 123.059,160.139 123.059,160.203 123.129,160.274 123.388,160.274 123.459,160.203 123.459,159.555 123.529,159.484 123.788,159.484 123.859,159.555 123.859,160.203 123.929,160.274 124.206,160.274 125.718,158.762 U5.48@125.718,157.788
SD_DQ13: U1.G15 U5.50 | length 20.1
  Top Layer w0.1: U1.G15@113.277,154.489 113.695,154.907 115.283,154.907 115.364,154.988 115.464,154.988 115.727,154.724 115.827,154.724 116.01,154.907 116.01,155.007 115.747,155.271 115.747,155.371 115.929,155.553 116.029,155.553 116.275,155.307 116.375,155.307 116.558,155.49 116.558,155.59 116.312,155.836 116.312,155.936 116.495,156.119 116.595,156.119 116.841,155.873 116.941,155.873 117.124,156.056 117.124,156.156 116.878,156.402 116.878,156.502 117.061,156.685 117.161,156.685 117.407,156.439 117.507,156.439 117.689,156.622 117.689,156.722 117.444,156.968 117.444,157.068 117.626,157.25 117.726,157.25 117.972,157.005 118.072,157.005 118.255,157.187 118.255,157.287 118.009,157.533 118.009,157.633 118.192,157.816 118.292,157.816 118.538,157.57 118.638,157.57 118.821,157.753 118.821,157.853 118.575,158.099 118.575,158.199 118.758,158.382 118.858,158.382 119.104,158.136 119.204,158.136 119.386,158.319 119.386,158.419 119.141,158.665 119.141,158.765 120.215,159.839 122.892,159.839 124.118,158.613 U5.50@124.118,157.788
SD_DQ14: U1.G16 U5.51 | length 20.1
  Top Layer w0.1: U1.G16@114.077,154.489 115.881,154.489 118.328,156.936 118.428,156.936 119.661,155.702 119.761,155.702 119.944,155.885 119.944,155.985 118.711,157.219 118.711,157.319 118.894,157.502 118.994,157.502 120.227,156.268 120.327,156.268 120.51,156.451 120.51,156.551 119.276,157.784 119.276,157.884 121.031,159.639 122.809,159.639 123.19,159.258 123.19,157.916 U5.51@123.318,157.788
SD_DQ15: U1.H15 U5.53 | length 19.6
  Top Layer w0.1: U1.H15@113.277,153.689 113.537,153.689 113.941,154.093 117.775,154.093 117.846,154.164 117.846,155.504 117.917,155.575 118.175,155.575 118.246,155.504 118.246,154.164 118.317,154.093 119.168,154.093 119.895,154.82 119.995,154.82 120.657,154.158 120.757,154.158 120.94,154.341 120.94,154.441 120.278,155.103 120.278,155.203 120.461,155.386 120.561,155.386 121.223,154.724 121.323,154.724 121.506,154.907 121.506,155.007 120.844,155.669 120.844,155.769 121.026,155.951 121.126,155.951 121.788,155.289 121.888,155.289 122.071,155.472 122.071,155.572 121.409,156.234 121.409,156.334 121.718,156.643 U5.53@121.718,157.788
SD_DQM0: U1.T15 U5.15 | length 24.6
  Top Layer w0.1: U1.T15@113.277,147.289 118.735,141.831 130.147,141.831 132.118,143.802 U5.15@132.118,146.504
SD_DQM1: U1.D14 U5.39 | length 24.7
  Top Layer w0.1: U1.D14@112.477,156.889 112.534,156.946 112.534,156.962 v1(112.831,157.259) 112.879,157.307 113.435,157.307 113.659,157.531 113.659,157.788 113.695,157.824 113.695,157.847 113.919,158.071 114.235,158.071 118.089,161.925 129.27,161.925 132.918,158.277 U5.39@132.918,157.788
SD_RAS_N: R50.1 U1.T14 | length 4.1
  Top Layer w0.254: U1.T14@112.522,147.123 112.649,146.996 v1(112.649,145.923)
  Bottom Layer w0.1: v1(112.649,145.923) 112.649,144.399 R50.1@113.613,143.435
SD_WE_N: R48.1 U1.N13 | length 36.1
  Top Layer w0.254: U1.N13@111.677,149.689 v1(112.014,149.352)
  Bottom Layer w0.1: v1(112.014,149.352) 113.522,149.352 113.593,149.281 113.593,148.661 113.664,148.59 113.922,148.59 113.993,148.661 113.993,149.281 114.064,149.352 114.322,149.352 114.393,149.281 114.393,148.661 114.464,148.59 114.722,148.59 114.793,148.661 114.793,149.281 114.864,149.352 115.122,149.352 115.193,149.281 115.193,148.661 115.264,148.59 115.522,148.59 115.593,148.661 115.593,149.281 115.664,149.352 115.922,149.352 115.993,149.281 115.993,148.661 116.064,148.59 116.322,148.59 116.393,148.661 116.393,149.281 116.464,149.352 116.722,149.352 116.793,149.281 116.793,148.661 116.864,148.59 117.122,148.59 117.193,148.661 117.193,149.281 117.264,149.352 117.522,149.352 117.593,149.281 117.593,148.661 117.664,148.59 117.922,148.59 117.993,148.661 117.993,149.281 118.064,149.352 118.322,149.352 118.393,149.281 118.393,148.661 118.464,148.59 118.722,148.59 118.793,148.661 118.793,149.281 118.864,149.352 119.122,149.352 119.193,149.281 119.193,148.661 119.264,148.59 119.522,148.59 119.593,148.661 119.593,149.281 119.664,149.352 119.922,149.352 119.993,149.281 119.993,148.661 120.064,148.59 120.322,148.59 120.393,148.661 120.393,149.281 120.464,149.352 120.722,149.352 120.793,149.281 120.793,148.661 120.864,148.59 121.122,148.59 121.193,148.661 121.193,149.281 121.264,149.352 121.522,149.352 121.593,149.281 121.593,148.661 121.664,148.59 121.922,148.59 121.993,148.661 121.993,149.281 122.064,149.352 122.322,149.352 122.393,149.281 122.393,148.661 122.464,148.59 122.722,148.59 122.793,148.661 122.793,149.281 122.864,149.352 123.122,149.352 123.193,149.281 123.193,148.661 123.264,148.59 123.522,148.59 123.593,148.661 123.593,149.281 123.664,149.352 123.922,149.352 123.993,149.281 123.993,148.661 124.064,148.59 124.322,148.59 124.393,148.661 124.393,149.281 124.464,149.352 124.901,149.352 124.972,149.281 124.972,149.169 125.043,149.098 125.301,149.098 125.372,149.169 125.372,149.281 125.443,149.352 125.701,149.352 125.772,149.281 125.772,149.169 125.843,149.098 126.101,149.098 126.172,149.169 126.172,149.281 126.243,149.352 126.501,149.352 126.572,149.281 126.572,149.169 126.643,149.098 126.901,149.098 126.972,149.169 126.972,149.281 127.043,149.352 R48.1@127.583,149.352
SDA: R22.1 U2.11 | length 1.9
  Top Layer w0.254: R22.1@105.151,105.918 U2.11@105.151,107.836
SSPI_CS_N: U1.R1 U2.18 | length 41.3
  Top Layer w0.254: U1.R1@102.077,148.089 101.092,147.104 101.092,143.891 v1(103.886,141.097) ; U2.18@110.241,113.411 v1(111.76,113.411)
  Bottom Layer w0.254: v1(103.886,141.097) 103.886,131.743 105.029,130.6 105.029,121.793 109.447,117.375 109.447,115.216 111.252,113.411 v1(111.76,113.411)
TCK: H1.1 U1.T10 | length 88.4
  Top Layer w0.1: v1(104.898,155.661) 105.109,155.661 105.119,155.671 105.435,155.671 105.445,155.661 105.623,155.661 v1@105.664,155.702 ; v1(106.934,169.418) 145.272,169.418 145.456,169.602 145.456,170.509 146.102,171.155 147.014,171.155 147.66,170.509 147.66,169.597 147.014,168.951 146.438,168.951 145.205,167.719 145.205,163.786 H1.1@146.558,162.433 ; U1.T10@109.277,147.289 110.661,145.905 v1(110.661,145.796)
  Bottom Layer w0.1: v1(104.898,155.661) 104.382,155.661 103.079,154.358 103.079,153.802 103.03,153.752 103.03,153.6 103.091,153.538 103.091,153.04 102.489,152.438 102.489,151.667 103.461,150.695 107.76,150.695 107.973,150.481 109.006,150.481 110.792,148.695 110.792,145.927 v1(110.661,145.796) ; v1(105.664,155.661) 106.934,156.931 107.019,156.931 107.111,156.839 107.444,156.839 107.679,157.075 107.679,157.408 107.444,157.643 107.111,157.643 106.934,157.82 v1(106.934,169.418)
TDI: H1.3 U1.R11 | length 80.2
  Top Layer w0.1: U1.R11@110.077,148.089 110.077,148.041 v1(110.39,147.728) ; v1(111.633,135.001) 111.633,135.935 111.485,136.083 111.485,136.417 111.633,136.565 111.633,136.946 113.117,138.43 141.224,138.43 147.882,145.088 147.882,161.153 147.669,161.366 147.669,163.579 146.393,163.579 145.456,164.517 145.456,165.429 146.558,166.531 H1.3@146.558,167.513
  Bottom Layer w0.1: v1(110.39,147.728) 110.259,147.597 110.259,138.291 111.402,137.148 111.402,135.232 v1(111.633,135.001)
TDO: H1.4 U1.M10 | length 72.1
  Top Layer w0.1: v1(106.489,158.054) 106.701,158.054 106.719,158.071 107.035,158.071 107.295,157.811 107.295,157.531 107.519,157.307 107.519,157.271 107.489,157.241 v1(107.277,157.241) ; v1(107.696,168.783) 145.288,168.783 H1.4@146.558,170.053 ; v1(108.839,150.079) 108.867,150.079 U1.M10@109.277,150.489
  Bottom Layer w0.1: v1(106.489,158.054) 106.278,158.265 106.278,169.601 106.678,170.001 107.159,170.001 107.696,169.464 v1(107.696,168.783) ; v1(107.277,157.241) 107.15,157.368 106.921,157.368 106.066,156.514 106.066,156.357 105.772,156.063 104.501,156.063 102.879,154.441 102.879,153.884 102.83,153.835 102.83,153.517 102.891,153.456 102.891,153.122 102.235,152.466 102.235,151.638 103.378,150.495 107.677,150.495 108.092,150.079 v1(108.839,150.079)
TMS: H1.2 U1.T11 | length 73.1
  Top Layer w0.1: U1.T11@110.077,147.289 111.252,146.114 v1(111.252,144.653) ; v1(111.887,136.25) 132.759,136.25 133.313,135.696 133.895,135.696 134.449,136.25 139.327,136.25 148.082,145.005 148.082,163.449 H1.2@146.558,164.973
  Bottom Layer w0.1: v1(111.252,144.653) 110.744,144.145 110.744,139.38 110.892,139.232 110.892,138.898 111.887,137.903 v1(111.887,136.25)
TX: U1.K2 U2.37 | length 38.6
  Top Layer w0.1: v1@96.134,123.825 U2.37@96.134,125.336 ; v1@99.314,152.781 100.904,152.781 101.179,152.506 102.458,152.506 ; 102.459,152.507 U1.K2@102.877,152.089
  Bottom Layer w0.1: v1(96.134,123.846) 93.472,126.508 93.472,147.57 96.176,150.274 97.15,150.274 97.157,150.281 97.27,150.281 99.509,152.52 99.509,152.661 v1(99.389,152.781)
USB_VBUS: R44.1 R45.2 U2.15 | length 19.9
  Top Layer w0.1: R44.1@104.775,96.003 105.927,97.155 R45.2@106.054,97.155 106.553,97.654 v1(106.553,98.044) ; U2.15@110.114,109.601 v1(111.506,109.601)
  Bottom Layer w0.1: v1(106.553,98.044) 108.331,98.044 112.776,102.489 112.776,108.331 v1(111.506,109.601)
VSYNC: P1.7 U1.B10 | length 27.1
  Top Layer w0.1: U1.B10@109.277,158.489 109.673,158.885 v1(109.72,158.885) ; P1.7@116.634,175.655 116.713,175.577 v1(116.713,174.625)
  Bottom Layer w0.1: v1(109.72,158.885) 109.72,159.317 110.003,159.599 110.003,166.264 111.898,168.159 111.898,168.259 111.589,168.568 111.589,168.668 111.772,168.851 111.872,168.851 112.181,168.542 112.281,168.542 112.464,168.725 112.464,168.825 112.155,169.134 112.155,169.234 112.337,169.417 112.437,169.417 112.747,169.108 112.847,169.108 113.029,169.29 113.029,169.39 112.72,169.7 112.72,169.8 112.903,169.982 113.003,169.982 113.312,169.673 113.412,169.673 113.595,169.856 113.595,169.956 113.286,170.265 113.286,170.365 113.469,170.548 113.569,170.548 113.878,170.239 113.978,170.239 114.161,170.422 114.161,170.522 113.852,170.831 113.852,170.931 114.035,171.114 114.135,171.114 114.444,170.805 114.544,170.805 114.73,170.991 114.73,171.184 114.917,171.37 115.109,171.37 115.292,171.553 115.292,171.653 115.126,171.819 115.126,171.919 115.309,172.102 115.409,172.102 115.575,171.936 115.675,171.936 115.858,172.119 115.858,172.219 115.513,172.563 115.513,172.663 115.696,172.846 115.796,172.846 116.141,172.502 116.241,172.502 116.713,172.974 v1(116.713,174.625)
Y2: P1.19 U1.B14 | length 27
  Top Layer w0.1: U1.B14@112.477,158.489 112.865,158.877 v1(112.903,158.877) ; P1.19@122.634,175.655 122.682,175.607 v1(122.682,174.117)
  Bottom Layer w0.1: v1(112.903,158.877) 112.903,159.705 112.882,159.726 112.882,160.06 113.117,160.295 113.559,160.295 117.563,164.299 117.563,164.465 117.764,164.665 117.929,164.665 118.145,164.881 118.145,164.981 117.957,165.169 117.957,165.269 118.139,165.451 118.239,165.451 118.427,165.263 118.527,165.263 118.71,165.446 118.71,165.546 118.522,165.734 118.522,165.834 118.705,166.017 118.805,166.017 118.993,165.829 119.093,165.829 119.276,166.012 119.276,166.112 119.088,166.3 119.088,166.4 119.271,166.583 119.371,166.583 119.559,166.395 119.659,166.395 119.842,166.578 119.842,166.678 119.654,166.866 119.654,166.966 119.837,167.148 119.937,167.148 120.125,166.961 120.225,166.961 120.407,167.143 120.407,167.243 120.219,167.431 120.219,167.531 120.402,167.714 120.502,167.714 120.69,167.526 120.79,167.526 120.973,167.709 120.973,167.809 120.785,167.997 120.785,168.097 120.968,168.28 121.068,168.28 121.256,168.092 121.356,168.092 121.539,168.275 121.539,168.375 121.351,168.563 121.351,168.663 121.534,168.846 121.634,168.846 121.822,168.658 121.922,168.658 122.104,168.84 122.104,168.94 121.916,169.128 121.916,169.228 122.099,169.411 122.199,169.411 122.387,169.223 122.487,169.223 122.682,169.418 v1(122.682,174.117)
Y3: P1.21 U1.C12 | length 27
  Top Layer w0.1: v1(109.714,158.1) 110.466,158.1 U1.C12@110.877,157.689 ; v1(123.636,174.117) P1.21@123.636,175.652
  Bottom Layer w0.1: v1(109.714,158.1) 109.967,158.1 110.109,158.242 110.178,158.242 110.195,158.259 112.92,158.259 114.152,159.491 114.152,159.933 114.387,160.168 115.337,160.168 123.636,168.467 v1(123.636,174.117)
Y4: P1.22 U1.C13 | length 27
  Top Layer w0.1: U1.C13@111.677,157.689 111.937,157.689 112.319,158.071 113.399,158.071 113.695,158.367 113.695,158.647 113.919,158.871 114.411,158.871 v1(114.486,158.945) ; v1(124.136,174.625) P1.22@124.136,175.652
  Bottom Layer w0.1: v1(114.486,158.945) 116.146,158.945 122.941,165.74 123.041,165.74 123.322,165.459 123.422,165.459 123.605,165.642 123.605,165.742 123.324,166.023 123.324,166.123 123.507,166.306 123.607,166.306 123.888,166.025 123.988,166.025 124.171,166.208 124.171,166.308 123.89,166.589 123.89,166.689 124.136,166.935 v1(124.136,174.625)
Y5: P1.20 U1.A15 | length 27
  Top Layer w0.1: U1.A15@113.277,159.289 113.284,159.296 v1(113.284,159.893) ; v1(123.136,174.625) P1.20@123.136,175.652
  Bottom Layer w0.1: v1(113.284,159.893) 113.83,159.893 116.727,162.791 116.827,162.791 116.835,162.782 116.935,162.782 117.118,162.965 117.118,163.065 117.11,163.074 117.11,163.174 117.37,163.434 117.47,163.434 117.669,163.235 117.769,163.235 117.952,163.418 117.952,163.518 117.753,163.717 117.753,163.817 117.936,163.999 118.036,163.999 118.235,163.801 118.335,163.801 118.518,163.984 118.518,164.084 118.319,164.282 118.319,164.382 118.502,164.565 118.602,164.565 118.8,164.366 118.9,164.366 119.083,164.549 119.083,164.649 118.885,164.848 118.885,164.948 119.067,165.131 119.167,165.131 119.366,164.932 119.466,164.932 119.649,165.115 119.649,165.215 119.45,165.414 119.45,165.514 119.633,165.696 119.733,165.696 119.932,165.498 120.032,165.498 120.215,165.681 120.215,165.781 120.016,165.979 120.016,166.079 120.199,166.262 120.299,166.262 120.497,166.063 120.597,166.063 120.78,166.246 120.78,166.346 120.582,166.545 120.582,166.645 120.764,166.828 120.864,166.828 121.063,166.629 121.163,166.629 121.346,166.812 121.346,166.912 121.147,167.111 121.147,167.211 121.33,167.393 121.43,167.393 121.629,167.195 121.729,167.195 121.912,167.378 121.912,167.478 121.713,167.676 121.713,167.776 121.896,167.959 121.996,167.959 122.194,167.76 122.294,167.76 122.477,167.943 122.477,168.043 122.279,168.242 122.279,168.342 123.136,169.199 v1(123.136,174.625)
Y6: P1.18 U1.A14 | length 27.1
  Top Layer w0.1: U1.A14@112.477,159.289 112.842,159.654 v1(112.842,160.589) ; P1.18@122.134,175.655 122.174,175.615 v1(122.174,174.625)
  Bottom Layer w0.1: v1(112.842,160.589) 115.881,163.627 115.881,163.727 115.835,163.772 115.835,163.872 116.018,164.055 116.118,164.055 116.164,164.01 116.264,164.01 116.493,164.239 116.493,164.339 116.307,164.524 116.307,164.624 116.49,164.807 116.59,164.807 116.775,164.621 116.875,164.621 117.058,164.804 117.058,164.904 116.873,165.09 116.873,165.19 117.056,165.372 117.156,165.372 117.341,165.187 117.441,165.187 117.624,165.37 117.624,165.47 117.439,165.655 117.439,165.755 117.621,165.938 117.721,165.938 117.907,165.753 118.007,165.753 118.19,165.936 118.19,166.036 118.004,166.221 118.004,166.321 118.187,166.504 118.287,166.504 118.472,166.318 118.572,166.318 118.755,166.501 118.755,166.601 118.57,166.787 118.57,166.887 118.753,167.07 118.853,167.07 119.038,166.884 119.138,166.884 119.321,167.067 119.321,167.167 119.136,167.352 119.136,167.452 119.318,167.635 119.418,167.635 119.604,167.45 119.704,167.45 119.887,167.633 119.887,167.733 119.701,167.918 119.701,168.018 119.884,168.201 119.984,168.201 120.169,168.016 120.269,168.016 120.452,168.198 120.452,168.298 120.267,168.484 120.267,168.584 120.45,168.767 120.55,168.767 120.735,168.581 120.835,168.581 121.018,168.764 121.018,168.864 120.833,169.049 120.833,169.149 121.016,169.332 121.116,169.332 121.301,169.147 121.401,169.147 121.584,169.33 121.584,169.43 121.398,169.615 121.398,169.715 121.581,169.898 121.681,169.898 121.867,169.713 121.967,169.713 122.174,169.92 v1(122.174,174.625)
Y7: P1.16 U1.A13 | length 27
  Top Layer w0.1: U1.A13@111.677,159.289 112.014,159.626 v1(112.014,160.02) ; P1.16@121.134,175.654 121.158,175.63 v1(121.158,174.625)
  Bottom Layer w0.1: v1(112.014,160.02) 112.014,161.671 115.153,164.81 115.295,164.81 115.507,165.022 115.507,165.164 115.692,165.349 115.692,165.449 115.475,165.667 115.475,165.767 115.657,165.949 115.757,165.949 115.975,165.732 116.075,165.732 116.258,165.915 116.258,166.015 116.04,166.232 116.04,166.332 116.223,166.515 116.323,166.515 116.541,166.298 116.641,166.298 116.823,166.48 116.823,166.58 116.606,166.798 116.606,166.898 116.789,167.081 116.889,167.081 117.106,166.863 117.206,166.863 117.389,167.046 117.389,167.146 117.172,167.364 117.172,167.464 117.354,167.646 117.454,167.646 117.672,167.429 117.772,167.429 117.955,167.612 117.955,167.712 117.737,167.929 117.737,168.029 117.92,168.212 118.02,168.212 118.238,167.995 118.338,167.995 118.52,168.177 118.52,168.277 118.303,168.495 118.303,168.595 118.486,168.778 118.586,168.778 118.803,168.56 118.903,168.56 119.086,168.743 119.086,168.843 118.869,169.061 118.869,169.161 119.051,169.343 119.151,169.343 119.369,169.126 119.469,169.126 119.652,169.309 119.652,169.409 119.434,169.626 119.434,169.726 119.617,169.909 119.717,169.909 119.935,169.692 120.035,169.692 120.217,169.874 120.217,169.974 120,170.192 120,170.292 120.183,170.475 120.283,170.475 120.5,170.257 120.6,170.257 121.158,170.815 v1(121.158,174.625)
Y8: P1.14 U1.B12 | length 27
  Top Layer w0.1: U1.B12@110.877,158.489 111.252,158.864 v1(111.252,158.877) ; P1.14@120.135,175.655 120.265,175.524 v1(120.265,174.621)
  Bottom Layer w0.1: v1(111.252,158.877) 111.252,159.827 111.814,160.389 111.814,162.487 115.712,166.385 115.712,166.485 115.494,166.702 115.494,166.802 115.677,166.985 115.777,166.985 115.995,166.768 116.095,166.768 116.288,166.961 116.288,167.061 116.071,167.279 116.071,167.379 116.254,167.562 116.354,167.562 116.571,167.344 116.671,167.344 116.854,167.527 116.854,167.627 116.636,167.844 116.636,167.944 116.819,168.127 116.919,168.127 117.137,167.91 117.237,167.91 117.42,168.093 117.42,168.193 117.202,168.41 117.202,168.51 117.385,168.693 117.485,168.693 117.702,168.475 117.802,168.475 117.985,168.658 117.985,168.758 117.768,168.976 117.768,169.076 117.951,169.259 118.051,169.259 118.268,169.041 118.368,169.041 118.551,169.224 118.551,169.324 118.333,169.541 118.333,169.641 118.516,169.824 118.616,169.824 118.834,169.607 118.934,169.607 119.117,169.79 119.117,169.89 118.899,170.107 118.899,170.207 119.082,170.39 119.182,170.39 119.4,170.173 119.5,170.173 119.682,170.355 119.682,170.455 119.465,170.673 119.465,170.773 119.648,170.956 119.748,170.956 119.965,170.738 120.065,170.738 120.265,170.938 v1(120.265,174.621)
Y9: P1.12 U1.B11 | length 27
  Top Layer w0.1: U1.B11@110.077,158.489 110.465,158.877 v1(110.49,158.877) ; v1(119.135,174.625) P1.12@119.135,175.655
  Bottom Layer w0.1: v1(110.49,158.877) 111.052,159.439 111.052,160.286 110.977,160.361 110.977,164.317 113.889,167.229 113.889,167.329 113.862,167.356 113.862,167.456 114.045,167.639 114.145,167.639 114.172,167.612 114.272,167.612 114.498,167.838 114.498,167.938 114.281,168.156 114.281,168.256 114.464,168.439 114.564,168.439 114.781,168.221 114.881,168.221 115.064,168.404 115.064,168.504 114.846,168.721 114.846,168.821 115.029,169.004 115.129,169.004 115.347,168.787 115.447,168.787 115.63,168.97 115.63,169.07 115.412,169.287 115.412,169.387 115.595,169.57 115.695,169.57 115.913,169.353 116.013,169.353 116.195,169.535 116.195,169.635 115.978,169.853 115.978,169.953 116.161,170.136 116.261,170.136 116.478,169.918 116.578,169.918 116.761,170.101 116.761,170.201 116.544,170.419 116.544,170.519 116.726,170.701 116.826,170.701 117.044,170.484 117.144,170.484 117.327,170.667 117.327,170.767 117.109,170.984 117.109,171.084 117.292,171.267 117.392,171.267 117.61,171.05 117.71,171.05 117.892,171.232 117.892,171.332 117.675,171.55 117.675,171.65 117.858,171.833 117.958,171.833 118.175,171.615 118.275,171.615 118.458,171.798 118.458,171.898 118.241,172.116 118.241,172.216 118.423,172.398 118.523,172.398 118.741,172.181 118.841,172.181 119.135,172.475 v1(119.135,174.625)
pads on no net: P1.1 P1.10 SCREW1.1 SCREW2.1 SCREW3.1 SCREW4.1 U1.A9 U1.B3 U1.B8 U1.B13 U1.B15 U1.B16 U1.C1 U1.C2 U1.C3 U1.C4 U1.C5 U1.C6 U1.C9 U1.C10 U1.C11 U1.C14 U1.C15 U1.C16 U1.D1 U1.D3 U1.D4 U1.D5 U1.D6 U1.D7 U1.D8 U1.D9 U1.D10 U1.D11 U1.D12 U1.D13 U1.E3 U1.E4 U1.E5 U1.E6 U1.E7 U1.E8 U1.E9 U1.E10 U1.E11 U1.E12 U1.E13 U1.E14 U1.F3 U1.F4 U1.F5 U1.F12 U1.F13 U1.F14 U1.G3 U1.G4 U1.G5 U1.G12 U1.G13 U1.G14 U1.H2 U1.H3 U1.H4 U1.H5 U1.H12 U1.H13 U1.H14 U1.J3 U1.J4 U1.J5 U1.J12 U1.J13 U1.K3 U1.K4 U1.K5 U1.K13 U1.K14 U1.K15 U1.L1 U1.L2 U1.L3 U1.L4 U1.L5 U1.L13 U1.L14 U1.L16 U1.M2 U1.M3 U1.M4 U1.M5 U1.M6 U1.M7 U1.M9 U1.M11 U1.M12 U1.M13 U1.N1 U1.N3 U1.N4 U1.N5 U1.N6 U1.N7 U1.N8 U1.N9 U1.N11 U1.N12 U1.N14 U1.N16 U1.P1 U1.P2 U1.P3 U1.P4 U1.P5 U1.P6 U1.P7 U1.P8 U1.P11 U1.P12 U1.P13 U1.P14 U1.P15 U1.R2 U1.R3 U1.R4 U1.R5 U1.R6 U1.R7 U1.R8 U1.R12 U1.R14 U1.T13 U2.4 U2.16 U2.26 U2.28 U2.29 U2.30 U2.32 U2.33 U2.34 U2.35 U2.38 U2.39 U5.40 U8.4 USB1.A6 USB1.A7 USB1.A8 USB1.B6 USB1.B7 USB1.B8 USB2.A8 USB2.B6 USB2.B7 USB2.B8
copper on no net: | length 14.2
  Top Layer w0.1: 93.345,126.873 93.594,126.624 93.594,125.336 ; 94.234,126.492 94.864,125.862 94.864,125.336 ; 96.134,107.836 96.363,107.607 v1(96.363,106.202) ; 105.024,125.336 105.024,125.971 106.561,127.508 107.188,127.508 107.442,127.254 ; v1(109.729,148.589) 109.778,148.59 110.077,148.889
  Top Layer w0.254: v1(101.473,148.54) 101.728,148.54 102.077,148.889 ; v1(103.272,149.246) 103.272,149.284 103.677,149.689 ; v1(104.029,148.489) 104.077,148.489 104.477,148.889 ; v1(104.14,149.352) 104.477,149.689
  Bottom Layer w0.1: v1(96.363,106.202) 96.52,106.045 96.52,104.267 ; v1(109.729,148.589) 110.109,148.209 110.109,148.082

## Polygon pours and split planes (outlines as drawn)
+5V on Inner2 (solid, remove dead copper): 87.022,103.749 105.49,103.749 105.49,88.615 87.022,88.615
GND on Inner1 (solid, remove dead copper): 76.2,182.626 151.257,182.626 151.257,78.486 76.2,78.486
+5V on Top Layer (solid, remove dead copper, pour order 0): 86.741,99.695 89.878,99.695 89.878,93.641 86.741,93.641
+3V3 on Inner2 (solid, remove dead copper): 77.597,185.674 159.766,185.674 159.766,76.2 77.597,76.2

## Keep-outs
Board Outline Layer:
  lines w0.254: 84.455,86.229 148.455,86.229 148.455,181.229 84.455,181.229 84.455,86.229

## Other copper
Top Layer:
  region net GND: 92.073,127.396 92.581,127.396 92.581,126.995 92.067,126.995 92.073,127
  region net GND: 93.983,96.848 94.491,96.848 94.491,96.446 93.977,96.446 93.983,96.452
  region net GND: 96.015,92.403 96.523,92.403 96.523,92.001 96.009,92.001 96.015,92.007
  region net +1V8: 123.143,105.828 123.651,105.828 123.651,105.426 123.138,105.426 123.143,105.431
  region net GND: 121.662,103.797 122.17,103.797 122.17,103.396 121.657,103.396 121.662,103.401
  region: 93.094,127.074 93.602,127.074 93.602,126.672 93.088,126.672 93.094,126.678
  region: 93.983,126.693 94.491,126.693 94.491,126.291 93.977,126.291 93.983,126.297
Bottom Layer:
  region net DONE: 110.366,137.361 110.874,137.361 110.874,136.959 110.36,136.959 110.366,136.965
  region net PROGRAMN: 108.588,136.577 109.096,136.577 109.096,136.176 108.582,136.176 108.588,136.181
  region net INITN: 101.984,127.455 102.492,127.455 102.492,127.053 101.978,127.053 101.984,127.059
  region: 109.791,148.257 110.231,148.511 110.432,148.164 109.987,147.907 109.989,147.914

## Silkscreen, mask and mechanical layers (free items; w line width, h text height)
Top Silkscreen Layer:
  text "JTAG" at 144.674,166.326 h3.05 r90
